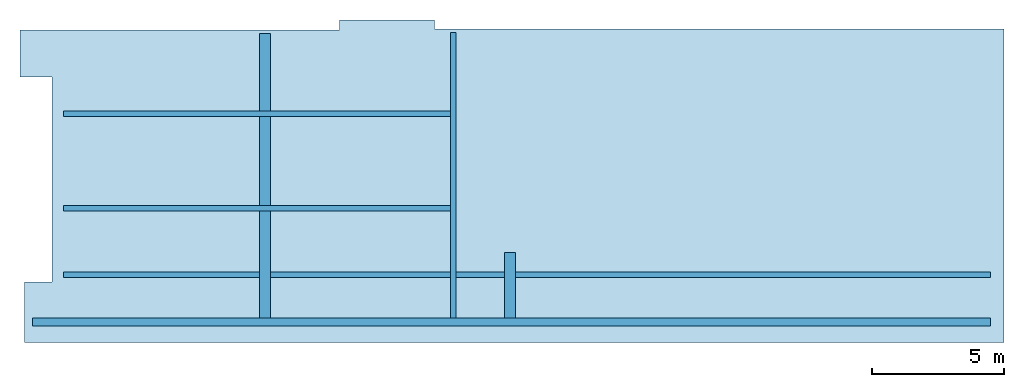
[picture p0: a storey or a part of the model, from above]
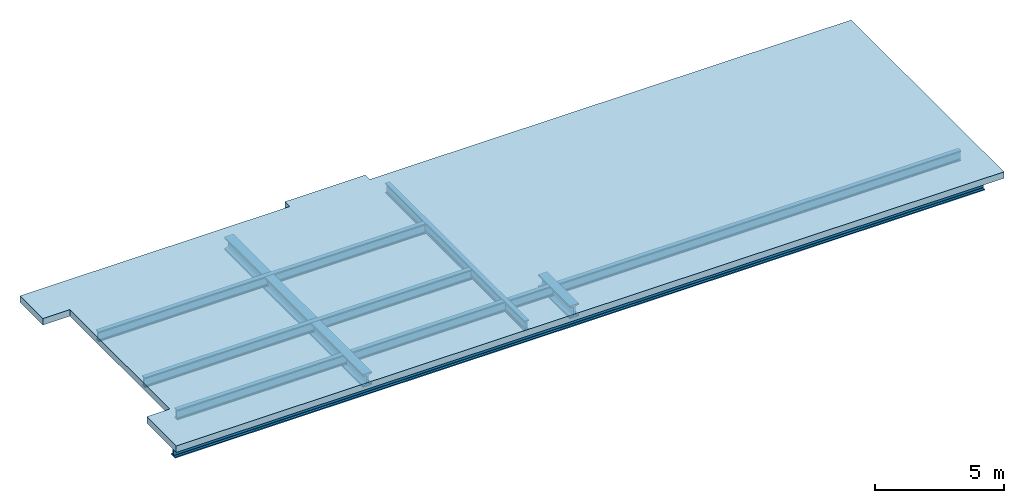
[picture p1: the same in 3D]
Properties of the parts of a building model (IFC4), part 1 of 2

# File
Description: ViewDefinition [DesignTransferView_V1.0]
File name: Project Number
Time: 2022-08-30T19:12:37
Written by: The EXPRESS Data Manager Version 5.02.0100.07 : 28 Aug 2013
Made in: 20200210_1400(x64) - Exporter 20.2.12.1 - Alternate UI 20.2.12.1
Comment: STEP Physical File produced by: The EXPRESS Data Manager Version 5.02.0100.07 : 28 Aug 2013 * Module: EDMstepFileFactory/EDMstandAlone * Creation date: Tue Aug 30 19:12:37 2022 * Host: DESKTOP-ASMPUQ8 * Database: C:\Users\PA\AppData\Local\Temp\d3cd8c80-7526-4842-971e-067392d3ef80\bd1fe66a-f83b-4d99-8f8f-0db7dfb2baac\ifc * Database version: 5507 * Database creation date: Tue Aug 30 19:12:32 2022 * Schema: IFC4 * Model: DataRepository.ifc * Model creation date: Tue Aug 30 19:12:32 2022 * Header model: DataRepository.ifc_HeaderModel * Header model creation date: Tue Aug 30 19:12:32 2022 * EDMuser: sdai-user * EDMgroup: sdai-group * License ID and type: 5605 : Permanent license. Expiry date: * EDMstepFileFactory options: 020000

# IfcProject, Project Number
LongName: NY 1114 6th Ave L15; Phase: Project Status

# IfcSite, Default
RefLatitude: 42, 21, 31, 181945; RefLongitude: -71, -3, -24, -263305; RefElevation: 0 ft

# IfcBuilding
Pset_BuildingCommon - Reference: Project Information; NumberOfStoreys: 3

# IfcBuildingStorey: Level:1/4" Head (3)
Pset_BuildingStoreyCommon - Reference: 1/4" Head
Name | LongName | Elevation (ft)
Level 3 | Level 3 | 24
Level 15 | Level 15 | 168
Level 16 | Level 16 | 181.083

# IfcAirTerminal: 10'-6" (2)
In: Level 15
Type - Pset_AirTerminalTypeCommon - Reference: 10'-6"; SlotWidth: 0.0833333 ft
Type - Pset_EnvironmentalImpactIndicators - Reference: 10'-6"
Name (Supply Diffuser with Plenum - Linear Slot - Hosted:10'-6":...)
2782970
2783304

# IfcAirTerminal: 12' (4)
In: Level 15
Type - Pset_AirTerminalTypeCommon - Reference: 12'; SlotWidth: 0.0833333 ft
Type - Pset_EnvironmentalImpactIndicators - Reference: 12'
Name (Supply Diffuser with Plenum - Linear Slot - Hosted:12':...)
2778098
2782745
2782873
2782875

# IfcAirTerminal: 16', Supply Diffuser with Plenum - Linear Slot - Hosted:16':2783469
In: Level 15
Type - Pset_AirTerminalTypeCommon - Reference: 16'; SlotWidth: 0.0833333 ft
Type - Pset_EnvironmentalImpactIndicators - Reference: 16'

# IfcAirTerminal: 16x10 (3)
In: Level 15
Type - Pset_AirTerminalTypeCommon - Reference: 16x10
Type - Pset_EnvironmentalImpactIndicators - Reference: 16x10
Pset_AirTerminalTypeCommon - sets with these values: 2
Group: Mechanical Supply Air 12
Name (Supply Diffuser - Sidewall:16x10:...)
2730207
2730213
2730216

# IfcAirTerminal: 20 x 20, Square Supply Diffuser (1):20 x 20:2646494
In: Level 15
Type - Classification: D3040100 Air Distribution Systems (Uniformat)
Type - Pset_AirTerminalTypeCommon - Reference: 20 x 20
Type - Pset_EnvironmentalImpactIndicators - Reference: 20 x 20
Pset_AirTerminalTypeCommon - sets with these values: 2

# IfcAirTerminal: 20x14 (3)
In: Level 15
Type - Pset_AirTerminalTypeCommon - Reference: 20x14
Type - Pset_EnvironmentalImpactIndicators - Reference: 20x14
Pset_AirTerminalTypeCommon - sets with these values: 2
Group: Mechanical Supply Air 7
Name (Supply Diffuser - Sidewall:20x14:...)
2730194
2730197
2730199

# IfcAirTerminal: 24x 24 (2)
In: Level 15
Type - Classification: D3040100 Air Distribution Systems (Uniformat)
Type - Pset_AirTerminalTypeCommon - Reference: 24x 24
Type - Pset_EnvironmentalImpactIndicators - Reference: 24x 24
Pset_AirTerminalTypeCommon - sets with these values: 2
Name (Square Supply Diffuser (1):24x 24:...)
2646642
2646688

# IfcAirTerminal: 32x12 (3)
In: Level 15
Type - Pset_AirTerminalTypeCommon - Reference: 32x12
Type - Pset_EnvironmentalImpactIndicators - Reference: 32x12
Pset_AirTerminalTypeCommon - sets with these values: 2
Name (Supply Diffuser - Sidewall:32x12:...) | Group
2730180 | Mechanical Supply Air 2
2730182 | Mechanical Supply Air 2
2730186 | Mechanical Supply Air 4

# IfcAirTerminal: 46'-6" (2)
In: Level 15
Type - Pset_AirTerminalTypeCommon - Reference: 46'-6"; SlotWidth: 0.0833333 ft
Type - Pset_EnvironmentalImpactIndicators - Reference: 46'-6"
Name (Supply Diffuser with Plenum - Linear Slot - Hosted:46'-6":...)
2783690
2783849

# IfcAirTerminal: 50x20, Supply Diffuser - Sidewall:50x20:2730433
In: Level 15
Type - Pset_AirTerminalTypeCommon - Reference: 50x20
Type - Pset_EnvironmentalImpactIndicators - Reference: 50x20
Pset_AirTerminalTypeCommon - sets with these values: 2
Group: Mechanical Supply Air 19

# IfcBeam: T Form Beam (4)
In: Level 16
Type - PredefinedType: BEAM; Material: Steel, 45-345
Type - Pset_BeamCommon - IsExternal: no; Reference: T Form Beam
Type - Pset_EnvironmentalImpactIndicators - Reference: T Form Beam
Type - Pset_ReinforcementBarPitchOfBeam - Reference: T Form Beam
Pset_BeamCommon - Slope: 0 deg; Roll: 0 deg
Pset_EnvironmentalImpactIndicators - sets with these values: 2
Name (UB-Universal Beam:T Form Beam:...) | Span (ft)
2719749 | 49.6875
2720074 | 49.0208
2720323 | 116.959
2722082 | 37.4165

# IfcBeam: T Form Beam 2 (2)
In: Level 16
Type - PredefinedType: BEAM; Material: Steel, 45-345
Type - Pset_BeamCommon - IsExternal: no; Reference: T Form Beam 2
Type - Pset_EnvironmentalImpactIndicators - Reference: T Form Beam 2
Type - Pset_ReinforcementBarPitchOfBeam - Reference: T Form Beam 2
Pset_BeamCommon - Slope: 0 deg; Roll: 0 deg
Pset_EnvironmentalImpactIndicators - sets with these values: 2
Name (UB-Universal Beam:T Form Beam 2:...) | Span (ft)
2721637 | 34.5559
2722027 | 7.31925

# IfcBeam: T Form Beam 3, UB-Universal Beam:T Form Beam 3:2722767
In: Level 16
Type - PredefinedType: BEAM; Material: Steel, 45-345
Type - Pset_BeamCommon - IsExternal: no; Reference: T Form Beam 3
Type - Pset_EnvironmentalImpactIndicators - Reference: T Form Beam 3
Type - Pset_ReinforcementBarPitchOfBeam - Reference: T Form Beam 3
Pset_BeamCommon - Slope: 0 deg; Roll: 0 deg; Span: 116.959 ft
Pset_EnvironmentalImpactIndicators - sets with these values: 2

# IfcBuildingElementProxy: Electrical Equipment, Electrical Equipment:Electrical Equipment:2730397
In: Level 15
Type - Pset_BuildingElementProxyCommon - IsExternal: no; Reference: Electrical Equipment
Type - Pset_EnvironmentalImpactIndicators - Reference: Electrical Equipment
Pset_BuildingElementProxyProvisionForVoid - Width: 2 ft; Height: 0.833333 ft; Depth: 2.5 ft

# IfcBuildingElementProxy: Mechanical Equipment_Unit 01, Mechanical Equipment_Unit 01:Mechanical Equipment_Unit 01:2730187
In: Level 15
Type - Pset_BuildingElementProxyCommon - IsExternal: no; Reference: Mechanical Equipment_Unit 01
Type - Pset_BuildingElementProxyProvisionForVoid - Width: 10.8333 ft; Height: 3.58333 ft; Depth: 10 ft
Type - Pset_EnvironmentalImpactIndicators - Reference: Mechanical Equipment_Unit 01

# IfcBuildingElementProxy: Radiator (4)
In: Level 15
Type - Pset_BuildingElementProxyCommon - IsExternal: no; Reference: Radiator
Type - Pset_EnvironmentalImpactIndicators - Reference: Radiator
Pset_BuildingElementProxyProvisionForVoid - Width: 1.72581 ft; Depth: 1.72581 ft
Name | Height (ft)
Radiator:Radiator:2247199 | 27.1817
Radiator1:Radiator:2247215 | 2.67119
Radiator2:Radiator:2247271 | 27.2291
Radiator3:Radiator:2247353 | 2.67119

# IfcCableCarrierFitting: Standard (9)
In: Level 15
Type - Pset_CableCarrierFittingTypeCommon - Reference: Standard
Type - Pset_EnvironmentalImpactIndicators - Reference: Standard
Pset_CableCarrierFittingTypeCommon - sets with these values: 2
Name (Conduit Elbow - Steel:Standard:...)
2730395
2730408
2730595
2730597
2730599
2730604
2730606
2730664
2730667

# IfcCableCarrierSegment: Conduit with Fittings:Conduit (16)
In: Level 15
Type - Pset_CableCarrierSegmentTypeCommon - Reference: Conduit
Type - Pset_EnvironmentalImpactIndicators - Reference: Conduit
Pset_CableCarrierSegmentTypeCommon - sets with these values: 2
Name (Conduit with Fittings:Conduit:...)
2730393
2730394
2730398
2730407
2730591
2730592
2730593
2730594
2730601
2730602
2730603
2730660
2730661
2730662
2730663
2730666

# IfcColumn: Generic (5)
In: Level 15
Type - PredefinedType: COLUMN; Classification: B1010200 Upper Floor Framing - Vertical Elements (Uniformat); Material: Default Wall
Type - Pset_ColumnCommon - IsExternal: no; Reference: Generic
Type - Pset_EnvironmentalImpactIndicators - Reference: Generic
Type - Pset_ReinforcementBarPitchOfColumn - Reference: Generic
Pset_ColumnCommon - Slope: 0 deg
Pset_EnvironmentalImpactIndicators - sets with these values: 2
Name (I-Rectangular:Generic:...)
2212022
2212228
2212427
2212525
2212709

# IfcCovering: Compound Ceiling:30" x 30" ACT System (3)
In: Level 15
Type - PredefinedType: CEILING
Type - Pset_CoveringCommon - IsExternal: no; Reference: 30" x 30" ACT System; ThermalTransmittance: 3.59055 kg/K/s3
Type - Pset_EnvironmentalImpactIndicators - Reference: 30" x 30" ACT System
Classification: C3030210 Suspended Ceilings - Acoustical (Uniformat); Material: Default 0.135417 ft, Acoustic Ceiling Tile 24 x 24 0.0520833 ft
Pset_CoveringCommon - Finish: Acoustic Ceiling Tile 24 x 24;
Name (Compound Ceiling:30" x 30" ACT System:...)
2594296
2594552
2594579

# IfcCovering: Compound Ceiling:GWB on Mtl. Stud (4)
In: Level 15
Type - PredefinedType: CEILING
Type - Pset_CoveringCommon - IsExternal: no; Reference: GWB on Mtl. Stud; ThermalTransmittance: 0.271518 kg/K/s3
Type - Pset_EnvironmentalImpactIndicators - Reference: GWB on Mtl. Stud
Classification: C3030220 Suspended Ceilings - Gypsum Board (Uniformat); Material: Metal Stud Layer 0.302083 ft
Name (Compound Ceiling:GWB on Mtl. Stud:...)
2593632
2593987
2776662
2776686

# IfcCovering: Pipe Insulation:Default (11)
In: Level 15
PredefinedType: INSULATION
Pset_CoveringCommon - IsExternal: no; Reference: Default
Pset_EnvironmentalImpactIndicators - Reference: Default
Name (Pipe Insulation:Default:...)
2776108
2776109
2776110
2776111
2776112
2776113
2776122
2776123
2776124
2776125
2776126

# IfcCurtainWall: Curtain Wall:Storefront (5)
In: Level 15
Type - Pset_CurtainWallCommon - IsExternal: no; Reference: Storefront
Type - Pset_EnvironmentalImpactIndicators - Reference: Storefront
Classification: B2020200 Curtain Walls (Uniformat)
Pset_CurtainWallCommon - IsExternal: yes
Name (Curtain Wall:Storefront:...)
2237436
2238658
2246862
2246942
2247033

# IfcCurtainWall: Curtain Wall:Storefront 02 (12)
In: Level 15
Type - Pset_CurtainWallCommon - IsExternal: no; Reference: Storefront 02
Type - Pset_EnvironmentalImpactIndicators - Reference: Storefront 02
Classification: B2020200 Curtain Walls (Uniformat)
Pset_CurtainWallCommon - IsExternal: yes
Name (Curtain Wall:Storefront 02:...)
2251181
2251577
2251802
2252624
2252727
2376070
2376076
2376082
2376088
2376094
2589335
2591836

# IfcDistributionPort (646)
Description: Flow
Name | FlowDirection | Group
Port_2616530 | SOURCEANDSINK
Port_2634564 | SOURCEANDSINK
Port_2642526 | SOURCEANDSINK
Port_2642614 | SOURCEANDSINK
Port_2642695 | SOURCEANDSINK
Port_2642750 | SOURCEANDSINK
Port_2642807 | SOURCEANDSINK
Port_2642872 | SOURCEANDSINK
Port_2642874 | SOURCEANDSINK
Port_2642875 | SOURCEANDSINK
Port_2642876 | SOURCEANDSINK
Port_2642877 | SOURCEANDSINK
Port_2642889 | SOURCEANDSINK
Port_2642944 | SOURCEANDSINK
Port_2642991 | SOURCEANDSINK
Port_2643043 | SOURCEANDSINK
Port_2643100 | SOURCEANDSINK
Port_2643161 | SOURCEANDSINK
Port_2643180 | SOURCEANDSINK
Port_2643225 | SOURCEANDSINK
Port_2643266 | SOURCEANDSINK
Port_2643285 | SOURCEANDSINK
Port_2643315 | SOURCEANDSINK
Port_2643362 | SOURCEANDSINK
Port_2643445 | SOURCEANDSINK
Port_2643491 | SOURCEANDSINK
Port_2643562 | SOURCEANDSINK
Port_2643622 | SOURCEANDSINK
Port_2643695 | SOURCEANDSINK
Port_2643761 | SOURCEANDSINK
Port_2643844 | SOURCEANDSINK
Port_2643890 | SOURCEANDSINK
Port_2643984 | SOURCEANDSINK
Port_2644073 | SOURCEANDSINK
Port_2644150 | SOURCEANDSINK
Port_2644226 | SOURCEANDSINK
Port_2645126 | SOURCEANDSINK
Port_2645178 | SOURCEANDSINK
Port_2645256 | SOURCEANDSINK
Port_2645257 | SOURCEANDSINK
Port_2645316 | SOURCEANDSINK
Port_2645411 | SOURCEANDSINK
Port_2645462 | SOURCEANDSINK
Port_2645515 | SOURCEANDSINK
Port_2645580 | SOURCEANDSINK
Port_2645619 | SOURCEANDSINK
Port_2645707 | SOURCEANDSINK
Port_2645776 | SOURCEANDSINK
Port_2645860 | SOURCEANDSINK
Port_2646268 | SOURCEANDSINK
Port_2646331 | SOURCEANDSINK
Port_2648358 | SOURCEANDSINK
3 x InPort_2730176 | SOURCEANDSINK | Mechanical Supply Air 2
OutPort_2730178 | SOURCEANDSINK | Mechanical Supply Air 2
2 x OutPort_2730181 | SOURCEANDSINK | Mechanical Supply Air 2
2 x OutPort_2730670 | SOURCEANDSINK | Mechanical Supply Air 2
3 x InPort_2730177 | SOURCEANDSINK | Mechanical Supply Air 2
OutPort_2730669 | SOURCEANDSINK | Mechanical Supply Air 2
2 x OutPort_2730184 | SOURCEANDSINK | Mechanical Supply Air 2
2 x InPort_2730179 | SOURCEANDSINK | Mechanical Supply Air 2
OutPort_2730180 | SOURCEANDSINK | Mechanical Supply Air 2
InPort_2730180 | SINK | Mechanical Supply Air 2
OutPort_2730179 | SOURCE | Mechanical Supply Air 2
InPort_2730182 | SINK | Mechanical Supply Air 2
OutPort_2730183 | SOURCE | Mechanical Supply Air 2
InPort_2730183 | SOURCEANDSINK | Mechanical Supply Air 2
2 x InPort_2730185 | SOURCEANDSINK | Mechanical Supply Air 4
2 x OutPort_2730675 | SOURCEANDSINK | Mechanical Supply Air 4
OutPort_2730186 | SOURCEANDSINK | Mechanical Supply Air 4
InPort_2730186 | SINK | Mechanical Supply Air 4
OutPort_2730185 | SOURCE | Mechanical Supply Air 4
InPort_2730188 | SOURCEANDSINK | Mechanical Supply Air 5
2 x OutPort_2730677 | SOURCEANDSINK | Mechanical Supply Air 5
InPort_2730189 | SOURCEANDSINK | Mechanical Supply Air 7
OutPort_2730191 | SOURCEANDSINK | Mechanical Supply Air 7
2 x InPort_2730190 | SOURCEANDSINK | Mechanical Supply Air 7
2 x OutPort_2730192 | SOURCEANDSINK | Mechanical Supply Air 7
OutPort_2730193 | SOURCEANDSINK | Mechanical Supply Air 7
3 x InPort_2730191 | SOURCEANDSINK | Mechanical Supply Air 7
2 x OutPort_2730196 | SOURCEANDSINK | Mechanical Supply Air 7
2 x OutPort_2730201 | SOURCEANDSINK | Mechanical Supply Air 7
InPort_2730193 | SOURCEANDSINK | Mechanical Supply Air 7
2 x OutPort_2730203 | SOURCEANDSINK | Mechanical Supply Air 7
InPort_2730194 | SINK | Mechanical Supply Air 7
OutPort_2730195 | SOURCE | Mechanical Supply Air 7
InPort_2730195 | SOURCEANDSINK | Mechanical Supply Air 7
InPort_2730197 | SINK | Mechanical Supply Air 7
OutPort_2730198 | SOURCE | Mechanical Supply Air 7
InPort_2730198 | SOURCEANDSINK | Mechanical Supply Air 7
OutPort_2730202 | SOURCEANDSINK | Mechanical Supply Air 7
InPort_2730199 | SINK | Mechanical Supply Air 7
OutPort_2730200 | SOURCE | Mechanical Supply Air 7
InPort_2730200 | SOURCEANDSINK | Mechanical Supply Air 7
InPort_2730202 | SOURCEANDSINK | Mechanical Supply Air 7
InPort_2730203 | SOURCEANDSINK | Mechanical Supply Air 7
OutPort_2730204 | SOURCEANDSINK | Mechanical Supply Air 7
Port_2730204 | SOURCEANDSINK | Mechanical Supply Air 7
InPort_2730205 | SOURCEANDSINK | Mechanical Supply Air 12
OutPort_2730209 | SOURCEANDSINK | Mechanical Supply Air 12
2 x InPort_2730206 | SOURCEANDSINK | Mechanical Supply Air 12
OutPort_2730208 | SOURCEANDSINK | Mechanical Supply Air 12
2 x OutPort_2730210 | SOURCEANDSINK | Mechanical Supply Air 12
InPort_2730207 | SINK | Mechanical Supply Air 12
OutPort_2730211 | SOURCE | Mechanical Supply Air 12
4 x InPort_2730209 | SOURCEANDSINK | Mechanical Supply Air 12
2 x OutPort_2730218 | SOURCEANDSINK | Mechanical Supply Air 12
2 x OutPort_2730212 | SOURCEANDSINK | Mechanical Supply Air 12
2 x OutPort_2730215 | SOURCEANDSINK | Mechanical Supply Air 12
InPort_2730211 | SOURCEANDSINK | Mechanical Supply Air 12
InPort_2730213 | SINK | Mechanical Supply Air 12
OutPort_2730214 | SOURCE | Mechanical Supply Air 12
InPort_2730214 | SOURCEANDSINK | Mechanical Supply Air 12
InPort_2730216 | SINK | Mechanical Supply Air 12
OutPort_2730217 | SOURCE | Mechanical Supply Air 12
InPort_2730217 | SOURCEANDSINK | Mechanical Supply Air 12
Port_2730219 | SOURCEANDSINK | Fire Protection Wet 2
InPort_2730219 | SOURCEANDSINK | Fire Protection Wet 2
2 x OutPort_2730403 | SOURCEANDSINK | Fire Protection Wet 2
2 x InPort_2730221 | SOURCEANDSINK | Fire Protection Wet 2
OutPort_2730223 | SOURCEANDSINK | Fire Protection Wet 2
2 x OutPort_2730227 | SOURCEANDSINK | Fire Protection Wet 2
InPort_2730223 | SOURCEANDSINK | Fire Protection Wet 2
2 x OutPort_2730258 | SOURCEANDSINK | Fire Protection Wet 2
2 x InPort_2730225 | SOURCEANDSINK | Fire Protection Wet 2
2 x OutPort_2730231 | SOURCEANDSINK | Fire Protection Wet 2
2 x InPort_2730229 | SOURCEANDSINK | Fire Protection Wet 2
OutPort_2730241 | SOURCEANDSINK | Fire Protection Wet 2
2 x InPort_2730233 | SOURCEANDSINK | Mechanical Supply Air 16
2 x OutPort_2730413 | SOURCEANDSINK | Mechanical Supply Air 16
OutPort_2730234 | SOURCEANDSINK | Mechanical Supply Air 16
InPort_2730234 | SOURCEANDSINK | Mechanical Supply Air 16
OutPort_2730235 | SOURCEANDSINK | Mechanical Supply Air 16
InPort_2730235 | SOURCEANDSINK | Mechanical Supply Air 16
OutPort_2730236 | SOURCEANDSINK | Mechanical Supply Air 16
Port_2730236 | SOURCEANDSINK | Mechanical Supply Air 16
3 x InPort_2730237 | SOURCEANDSINK | Fire Protection Wet 2
2 x OutPort_2730400 | SOURCEANDSINK | Fire Protection Wet 2
2 x OutPort_2730249 | SOURCEANDSINK | Fire Protection Wet 2
OutPort_2730238 | SOURCEANDSINK | Fire Protection Wet 2
InPort_2730238 | SOURCEANDSINK | Fire Protection Wet 2
2 x OutPort_2730436 | SOURCEANDSINK | Fire Protection Wet 2
InPort_2730241 | SOURCEANDSINK | Fire Protection Wet 2
OutPort_2730246 | SOURCEANDSINK | Fire Protection Wet 2
InPort_2730243 | SINK | Fire Protection Wet 2
OutPort_2730244 | SOURCE | Fire Protection Wet 2
InPort_2730244 | SOURCEANDSINK | Fire Protection Wet 2
2 x OutPort_2730248 | SOURCEANDSINK | Fire Protection Wet 2
InPort_2730246 | SOURCEANDSINK | Fire Protection Wet 2
InPort_2730248 | SOURCEANDSINK | Fire Protection Wet 2
InPort_2730252 | SINK | Fire Protection Wet 2
OutPort_2730253 | SOURCE | Fire Protection Wet 2
InPort_2730253 | SOURCEANDSINK | Fire Protection Wet 2
2 x OutPort_2730257 | SOURCEANDSINK | Fire Protection Wet 2
2 x InPort_2730255 | SOURCEANDSINK | Fire Protection Wet 2
2 x OutPort_2730264 | SOURCEANDSINK | Fire Protection Wet 2
InPort_2730257 | SOURCEANDSINK | Fire Protection Wet 2
InPort_2730261 | SINK | Fire Protection Wet 2
OutPort_2730262 | SOURCE | Fire Protection Wet 2
InPort_2730262 | SOURCEANDSINK | Fire Protection Wet 2
2 x InPort_2730266 | SOURCEANDSINK | Fire Protection Wet 2
2 x OutPort_2730349 | SOURCEANDSINK | Fire Protection Wet 2
2 x OutPort_2730270 | SOURCEANDSINK | Fire Protection Wet 2
2 x InPort_2730268 | SOURCEANDSINK | Fire Protection Wet 2
2 x OutPort_2730274 | SOURCEANDSINK | Fire Protection Wet 2
2 x InPort_2730272 | SOURCEANDSINK | Fire Protection Wet 2
OutPort_2730276 | SOURCEANDSINK | Fire Protection Wet 2
InPort_2730276 | SOURCEANDSINK | Fire Protection Wet 2
OutPort_2730280 | SOURCEANDSINK | Fire Protection Wet 2
Port_2730278 | SOURCEANDSINK | Fire Protection Wet 2
InPort_2730278 | SOURCEANDSINK | Fire Protection Wet 2
2 x OutPort_2730282 | SOURCEANDSINK | Fire Protection Wet 2
InPort_2730280 | SOURCEANDSINK | Fire Protection Wet 2
InPort_2730282 | SOURCEANDSINK | Fire Protection Wet 2
OutPort_2730283 | SOURCEANDSINK | Fire Protection Wet 2
InPort_2730283 | SOURCEANDSINK | Fire Protection Wet 2
OutPort_2730399 | SOURCEANDSINK | Fire Protection Wet 2
2 x InPort_2730286 | SOURCEANDSINK | Fire Protection Wet 2
2 x OutPort_2730347 | SOURCEANDSINK | Fire Protection Wet 2
OutPort_2730290 | SOURCEANDSINK | Fire Protection Wet 2
2 x InPort_2730288 | SOURCEANDSINK | Fire Protection Wet 2
2 x OutPort_2730297 | SOURCEANDSINK | Fire Protection Wet 2
2 x OutPort_2730337 | SOURCEANDSINK | Fire Protection Wet 2
2 x InPort_2730290 | SOURCEANDSINK | Fire Protection Wet 2
OutPort_2730291 | SOURCEANDSINK | Fire Protection Wet 2
OutPort_2730327 | SOURCEANDSINK | Fire Protection Wet 2
InPort_2730291 | SOURCEANDSINK | Fire Protection Wet 2
2 x OutPort_2730343 | SOURCEANDSINK | Fire Protection Wet 2
InPort_2730294 | SINK | Fire Protection Wet 2
OutPort_2730295 | SOURCE | Fire Protection Wet 2
InPort_2730295 | SOURCEANDSINK | Fire Protection Wet 2
2 x InPort_2730299 | SOURCEANDSINK | Fire Protection Wet 2
2 x OutPort_2730367 | SOURCEANDSINK | Fire Protection Wet 2
OutPort_2730301 | SOURCEANDSINK | Fire Protection Wet 2
InPort_2730301 | SOURCEANDSINK | Fire Protection Wet 2
2 x OutPort_2730319 | SOURCEANDSINK | Fire Protection Wet 2
2 x InPort_2730303 | SOURCEANDSINK | Fire Protection Wet 2
2 x OutPort_2730307 | SOURCEANDSINK | Fire Protection Wet 2
2 x OutPort_2730371 | SOURCEANDSINK | Fire Protection Wet 2
2 x InPort_2730305 | SOURCEANDSINK | Fire Protection Wet 2
OutPort_2730309 | SOURCEANDSINK | Fire Protection Wet 2
InPort_2730309 | SOURCEANDSINK | Fire Protection Wet 2
OutPort_2730311 | SOURCEANDSINK | Fire Protection Wet 2
InPort_2730311 | SOURCEANDSINK | Fire Protection Wet 2
2 x OutPort_2730378 | SOURCEANDSINK | Fire Protection Wet 2
InPort_2730313 | SINK | Fire Protection Wet 2
OutPort_2730314 | SOURCE | Fire Protection Wet 2
InPort_2730314 | SOURCEANDSINK | Fire Protection Wet 2
OutPort_2730318 | SOURCEANDSINK | Fire Protection Wet 2
2 x InPort_2730316 | SOURCEANDSINK | Fire Protection Wet 2
2 x OutPort_2730361 | SOURCEANDSINK | Fire Protection Wet 2
2 x OutPort_2730325 | SOURCEANDSINK | Fire Protection Wet 2
2 x InPort_2730318 | SOURCEANDSINK | Fire Protection Wet 2
OutPort_2730357 | SOURCEANDSINK | Fire Protection Wet 2
InPort_2730322 | SINK | Fire Protection Wet 2
OutPort_2730323 | SOURCE | Fire Protection Wet 2
InPort_2730323 | SOURCEANDSINK | Fire Protection Wet 2
InPort_2730327 | SOURCEANDSINK | Fire Protection Wet 2
2 x OutPort_2730333 | SOURCEANDSINK | Fire Protection Wet 2
2 x InPort_2730329 | SOURCEANDSINK | Fire Protection Wet 2
2 x OutPort_2730335 | SOURCEANDSINK | Fire Protection Wet 2
2 x InPort_2730331 | SOURCEANDSINK | Fire Protection Wet 2
2 x InPort_2730339 | SOURCEANDSINK | Fire Protection Wet 2
2 x OutPort_2730351 | SOURCEANDSINK | Fire Protection Wet 2
2 x InPort_2730341 | SOURCEANDSINK | Fire Protection Wet 2
2 x InPort_2730345 | SOURCEANDSINK | Fire Protection Wet 2
2 x OutPort_2730355 | SOURCEANDSINK | Fire Protection Wet 2
Port_2730353 | SOURCEANDSINK | Fire Protection Wet 2
InPort_2730353 | SOURCEANDSINK | Fire Protection Wet 2
InPort_2730357 | SOURCEANDSINK | Fire Protection Wet 2
2 x OutPort_2730363 | SOURCEANDSINK | Fire Protection Wet 2
2 x InPort_2730359 | SOURCEANDSINK | Fire Protection Wet 2
2 x InPort_2730365 | SOURCEANDSINK | Fire Protection Wet 2
2 x OutPort_2730373 | SOURCEANDSINK | Fire Protection Wet 2
2 x InPort_2730369 | SOURCEANDSINK | Fire Protection Wet 2
InPort_2730375 | SINK | Fire Protection Wet 2
OutPort_2730376 | SOURCE | Fire Protection Wet 2
InPort_2730376 | SOURCEANDSINK | Fire Protection Wet 2
InPort_2730378 | SOURCEANDSINK | Fire Protection Wet 2
OutPort_2730379 | SOURCEANDSINK | Fire Protection Wet 2
InPort_2730379 | SOURCEANDSINK | Fire Protection Wet 2
2 x InPort_2730382 | SOURCEANDSINK | Fire Protection Wet 11
2 x OutPort_2730391 | SOURCEANDSINK | Fire Protection Wet 11
2 x OutPort_2730387 | SOURCEANDSINK | Fire Protection Wet 11
InPort_2730384 | SINK | Fire Protection Wet 11
OutPort_2730385 | SOURCE | Fire Protection Wet 11
InPort_2730385 | SOURCEANDSINK | Fire Protection Wet 11
InPort_2730389 | SOURCEANDSINK | Fire Protection Wet 11
Port_2730389 | SOURCEANDSINK | Fire Protection Wet 11
Port_2730393 | SOURCEANDSINK
InPort_2730393 | SOURCEANDSINK
2 x OutPort_2730395 | SOURCEANDSINK
InPort_2730394 | SOURCEANDSINK
Port_2730394 | SOURCEANDSINK
InPort_2730398 | SOURCEANDSINK
2 x OutPort_2730408 | SOURCEANDSINK
Port_2730398 | SOURCEANDSINK
2 x InPort_2730399 | SOURCEANDSINK | Fire Protection Wet 2
2 x OutPort_2730404 | SOURCEANDSINK | Fire Protection Wet 2
InPort_2730403 | SOURCEANDSINK | Fire Protection Wet 2
InPort_2730407 | SOURCEANDSINK
Port_2730407 | SOURCEANDSINK
Port_2730410 | SOURCEANDSINK | Mechanical Supply Air 16
InPort_2730410 | SOURCEANDSINK | Mechanical Supply Air 16
2 x OutPort_2730412 | SOURCEANDSINK | Mechanical Supply Air 16
2 x InPort_2730411 | SOURCEANDSINK | Mechanical Supply Air 16
2 x InPort_2730414 | SOURCEANDSINK | Hydronic Supply 1
2 x OutPort_2730420 | SOURCEANDSINK | Hydronic Supply 1
2 x OutPort_2730495 | SOURCEANDSINK | Hydronic Supply 1
2 x InPort_2730416 | SOURCEANDSINK | Hydronic Supply 1
2 x OutPort_2730543 | SOURCEANDSINK | Hydronic Supply 1
2 x OutPort_2730426 | SOURCEANDSINK | Hydronic Supply 1
2 x InPort_2730418 | SOURCEANDSINK | Hydronic Supply 1
OutPort_2730422 | SOURCEANDSINK | Hydronic Supply 1
InPort_2730422 | SOURCEANDSINK | Hydronic Supply 1
2 x OutPort_2730544 | SOURCEANDSINK | Hydronic Supply 1
2 x InPort_2730424 | SOURCEANDSINK | Hydronic Supply 1
2 x OutPort_2730430 | SOURCEANDSINK | Hydronic Supply 1
Port_2730428 | SOURCEANDSINK | Hydronic Supply 1
InPort_2730428 | SOURCEANDSINK | Hydronic Supply 1
InPort_2730432 | SOURCEANDSINK | Mechanical Supply Air 19
OutPort_2730433 | SOURCEANDSINK | Mechanical Supply Air 19
Port_2730432 | SOURCEANDSINK | Mechanical Supply Air 19
InPort_2730433 | SINK | Mechanical Supply Air 19
OutPort_2730432 | SOURCE | Mechanical Supply Air 19
2 x InPort_2730434 | SOURCEANDSINK | Fire Protection Wet 2
2 x OutPort_2730440 | SOURCEANDSINK | Fire Protection Wet 2
InPort_2730438 | SOURCEANDSINK | Fire Protection Wet 2
Port_2730438 | SOURCEANDSINK | Fire Protection Wet 2
2 x InPort_2730442 | SOURCEANDSINK | Other 1
2 x OutPort_2730475 | SOURCEANDSINK | Other 1
OutPort_2730473 | SOURCEANDSINK | Other 1
2 x InPort_2730444 | SOURCEANDSINK | Fire Protection Wet 14
2 x OutPort_2730450 | SOURCEANDSINK | Fire Protection Wet 14
OutPort_2730446 | SOURCEANDSINK | Fire Protection Wet 14
Port_2730446 | SINK | Fire Protection Wet 14
2 x InPort_2730448 | SOURCEANDSINK | Fire Protection Wet 14
2 x OutPort_2730461 | SOURCEANDSINK | Fire Protection Wet 14
Port_2730452 | SOURCEANDSINK | Fire Protection Wet 16
InPort_2730452 | SOURCEANDSINK | Fire Protection Wet 16
2 x OutPort_2730457 | SOURCEANDSINK | Fire Protection Wet 16
InPort_2730454 | SINK | Fire Protection Wet 16
OutPort_2730455 | SOURCE | Fire Protection Wet 16
InPort_2730455 | SOURCEANDSINK | Fire Protection Wet 16
InPort_2730459 | SOURCEANDSINK | Fire Protection Wet 14
Port_2730459 | SOURCEANDSINK | Fire Protection Wet 14
InPort_2730463 | SOURCEANDSINK | Other 1
2 x OutPort_2730467 | SOURCEANDSINK | Other 1
Port_2730463 | SOURCEANDSINK | Other 1
2 x InPort_2730465 | SOURCEANDSINK | Other 1
InPort_2730467 | SOURCEANDSINK | Other 1
OutPort_2730468 | SOURCEANDSINK | Other 1
Port_2730468 | SOURCEANDSINK | Other 1
2 x InPort_2730471 | SOURCEANDSINK | Other 1
2 x OutPort_2730491 | SOURCEANDSINK | Other 1
2 x OutPort_2730483 | SOURCEANDSINK | Other 1
InPort_2730473 | SOURCEANDSINK | Other 1
OutPort_2730477 | SOURCEANDSINK | Other 1
InPort_2730477 | SOURCEANDSINK | Other 1
2 x OutPort_2730489 | SOURCEANDSINK | Other 1
InPort_2730479 | SOURCEANDSINK | Other 1
2 x OutPort_2730485 | SOURCEANDSINK | Other 1
Port_2730479 | SOURCEANDSINK | Other 1
2 x InPort_2730481 | SOURCEANDSINK | Other 1
2 x InPort_2730487 | SOURCEANDSINK | Other 1
2 x InPort_2730493 | SOURCEANDSINK | Hydronic Supply 1
2 x OutPort_2730499 | SOURCEANDSINK | Hydronic Supply 1
Port_2730497 | SOURCEANDSINK | Hydronic Supply 1
InPort_2730497 | SOURCEANDSINK | Hydronic Supply 1
2 x InPort_2730501 | SOURCEANDSINK | Hydronic Supply 3
2 x OutPort_2730507 | SOURCEANDSINK | Hydronic Supply 3
2 x OutPort_2730521 | SOURCEANDSINK | Hydronic Supply 3
2 x InPort_2730503 | SOURCEANDSINK | Hydronic Supply 3
2 x OutPort_2730573 | SOURCEANDSINK | Hydronic Supply 3
2 x OutPort_2730513 | SOURCEANDSINK | Hydronic Supply 3
2 x InPort_2730505 | SOURCEANDSINK | Hydronic Supply 3
OutPort_2730509 | SOURCEANDSINK | Hydronic Supply 3
InPort_2730509 | SOURCEANDSINK | Hydronic Supply 3
2 x OutPort_2730574 | SOURCEANDSINK | Hydronic Supply 3
2 x InPort_2730511 | SOURCEANDSINK | Hydronic Supply 3
2 x OutPort_2730517 | SOURCEANDSINK | Hydronic Supply 3
Port_2730515 | SOURCEANDSINK | Hydronic Supply 3
InPort_2730515 | SOURCEANDSINK | Hydronic Supply 3
2 x InPort_2730519 | SOURCEANDSINK | Hydronic Supply 3
2 x OutPort_2730525 | SOURCEANDSINK | Hydronic Supply 3
InPort_2730523 | SOURCEANDSINK | Hydronic Supply 3
Port_2730523 | SOURCEANDSINK | Hydronic Supply 3
2 x InPort_2730527 | SOURCEANDSINK | Hydronic Supply 1
2 x OutPort_2730531 | SOURCEANDSINK | Hydronic Supply 1
2 x OutPort_2730535 | SOURCEANDSINK | Hydronic Supply 1
Port_2730529 | SOURCEANDSINK | Hydronic Supply 1
InPort_2730529 | SOURCEANDSINK | Hydronic Supply 1
2 x InPort_2730533 | SOURCEANDSINK | Hydronic Supply 1
2 x OutPort_2730539 | SOURCEANDSINK | Hydronic Supply 1
2 x InPort_2730537 | SOURCEANDSINK | Hydronic Supply 1
2 x OutPort_2730547 | SOURCEANDSINK | Hydronic Supply 1
2 x InPort_2730541 | SOURCEANDSINK | Hydronic Supply 1
InPort_2730543 | SOURCEANDSINK | Hydronic Supply 1
2 x InPort_2730549 | SOURCEANDSINK | Hydronic Supply 3
2 x OutPort_2730557 | SOURCEANDSINK | Hydronic Supply 3
2 x OutPort_2730553 | SOURCEANDSINK | Hydronic Supply 3
2 x InPort_2730551 | SOURCEANDSINK | Hydronic Supply 3
2 x OutPort_2730567 | SOURCEANDSINK | Hydronic Supply 3
2 x InPort_2730555 | SOURCEANDSINK | Hydronic Supply 3
2 x OutPort_2730561 | SOURCEANDSINK | Hydronic Supply 3
2 x InPort_2730559 | SOURCEANDSINK | Hydronic Supply 3
2 x OutPort_2730577 | SOURCEANDSINK | Hydronic Supply 3
2 x InPort_2730563 | SOURCEANDSINK | Hydronic Supply 3
2 x InPort_2730565 | SOURCEANDSINK | Hydronic Supply 3
2 x OutPort_2730571 | SOURCEANDSINK | Hydronic Supply 3
Port_2730569 | SOURCEANDSINK | Hydronic Supply 3
InPort_2730569 | SOURCEANDSINK | Hydronic Supply 3
InPort_2730573 | SOURCEANDSINK | Hydronic Supply 3
InPort_2730579 | SOURCEANDSINK | Hydronic Supply 7
2 x OutPort_2730583 | SOURCEANDSINK | Hydronic Supply 7
Port_2730579 | SOURCEANDSINK | Hydronic Supply 7
Port_2730581 | SOURCEANDSINK | Hydronic Supply 7
InPort_2730581 | SOURCEANDSINK | Hydronic Supply 7
InPort_2730585 | SOURCEANDSINK | Hydronic Supply 9
2 x OutPort_2730589 | SOURCEANDSINK | Hydronic Supply 9
Port_2730585 | SOURCEANDSINK | Hydronic Supply 9
Port_2730587 | SOURCEANDSINK | Hydronic Supply 9
InPort_2730587 | SOURCEANDSINK | Hydronic Supply 9
2 x Port_2730591 | SOURCEANDSINK
2 x InPort_2730592 | SOURCEANDSINK
OutPort_2730599 | SOURCEANDSINK
2 x OutPort_2730595 | SOURCEANDSINK
2 x InPort_2730593 | SOURCEANDSINK
2 x OutPort_2730597 | SOURCEANDSINK
InPort_2730594 | SOURCEANDSINK
Port_2730594 | SOURCEANDSINK
Port_2730599 | SOURCEANDSINK
Port_2730601 | SOURCEANDSINK
InPort_2730601 | SOURCEANDSINK
2 x OutPort_2730604 | SOURCEANDSINK
2 x InPort_2730602 | SOURCEANDSINK
2 x OutPort_2730606 | SOURCEANDSINK
Port_2730603 | SOURCEANDSINK
InPort_2730603 | SOURCEANDSINK
InPort_2730608 | SOURCEANDSINK | Other 4
2 x OutPort_2730634 | SOURCEANDSINK | Other 4
Port_2730608 | SOURCEANDSINK | Other 4
2 x InPort_2730610 | SOURCEANDSINK | Other 4
2 x OutPort_2730618 | SOURCEANDSINK | Other 4
OutPort_2730612 | SOURCEANDSINK | Other 4
2 x InPort_2730612 | SOURCEANDSINK | Other 4
2 x OutPort_2730629 | SOURCEANDSINK | Other 4
OutPort_2730613 | SOURCEANDSINK | Other 4
Port_2730613 | SOURCEANDSINK | Other 4
InPort_2730616 | SOURCEANDSINK | Other 4
Port_2730616 | SOURCEANDSINK | Other 4
2 x InPort_2730620 | SOURCEANDSINK | Other 4
2 x OutPort_2730632 | SOURCEANDSINK | Other 4
OutPort_2730628 | SOURCEANDSINK | Other 4
Port_2730622 | SOURCEANDSINK | Other 4
InPort_2730622 | SOURCEANDSINK | Other 4
2 x InPort_2730624 | SOURCEANDSINK | Other 4
2 x OutPort_2730638 | SOURCEANDSINK | Other 4
Port_2730626 | SOURCEANDSINK | Other 4
InPort_2730626 | SOURCEANDSINK | Other 4
2 x InPort_2730628 | SOURCEANDSINK | Other 4
2 x OutPort_2730645 | SOURCEANDSINK | Other 4
InPort_2730634 | SOURCEANDSINK | Other 4
OutPort_2730635 | SOURCEANDSINK | Other 4
InPort_2730635 | SOURCEANDSINK | Other 4
2 x OutPort_2730654 | SOURCEANDSINK | Other 4
InPort_2730640 | SOURCEANDSINK | Other 4
2 x OutPort_2730648 | SOURCEANDSINK | Other 4
Port_2730640 | SOURCEANDSINK | Other 4
2 x InPort_2730642 | SOURCEANDSINK | Other 4
OutPort_2730644 | SOURCEANDSINK | Other 4
2 x InPort_2730644 | SOURCEANDSINK | Other 4
2 x OutPort_2730655 | SOURCEANDSINK | Other 4
InPort_2730650 | SOURCEANDSINK | Other 4
2 x OutPort_2730658 | SOURCEANDSINK | Other 4
Port_2730650 | SOURCEANDSINK | Other 4
2 x InPort_2730652 | SOURCEANDSINK | Other 4
InPort_2730654 | SOURCEANDSINK | Other 4
2 x Port_2730660 | SOURCEANDSINK
2 x Port_2730661 | SOURCEANDSINK
2 x InPort_2730662 | SOURCEANDSINK
2 x OutPort_2730667 | SOURCEANDSINK
2 x OutPort_2730664 | SOURCEANDSINK
InPort_2730663 | SOURCEANDSINK
Port_2730663 | SOURCEANDSINK
Port_2730666 | SOURCEANDSINK
InPort_2730666 | SOURCEANDSINK
InPort_2730669 | SOURCEANDSINK | Mechanical Supply Air 5
OutPort_2730676 | SOURCEANDSINK | Mechanical Supply Air 5
InPort_2730669 | SOURCEANDSINK | Mechanical Supply Air 4
OutPort_2730671 | SOURCEANDSINK | Mechanical Supply Air 4
InPort_2730671 | SOURCEANDSINK | Mechanical Supply Air 4
2 x OutPort_2730673 | SOURCEANDSINK | Mechanical Supply Air 4
3 x InPort_2730672 | SOURCEANDSINK | Mechanical Supply Air 4
OutPort_2730674 | SOURCEANDSINK | Mechanical Supply Air 4
InPort_2730676 | SOURCEANDSINK | Mechanical Supply Air 5

# IfcDoor: 36" x 102" (4)
In: Level 15
Type - PredefinedType: DOOR; ParameterTakesPrecedence: no; Material: Steel, Galvanized
Type - Pset_DoorCommon - IsExternal: no; Reference: 36" x 102"
Type - Pset_EnvironmentalImpactIndicators - Reference: 36" x 102"
OverallHeight: 8.53281 ft; OverallWidth: 3.06562 ft
Pset_DoorCommon - IsExternal: yes
Name (Door Single Panel:36" x 102":...)
2235835
2235964
2591388
2591432

# IfcDoor: 38" x 102" (2)
In: Level 15
Type - PredefinedType: DOOR; ParameterTakesPrecedence: no; Material: Steel, Galvanized
Type - Pset_DoorCommon - IsExternal: no; Reference: 38" x 102"
Type - Pset_EnvironmentalImpactIndicators - Reference: 38" x 102"
OverallHeight: 8.53281 ft; OverallWidth: 3.23228 ft
Pset_DoorCommon - IsExternal: yes
Name (Door Single Panel:38" x 102":...)
2234826
2235436

# IfcDoor: 44" x 102", Door Single Panel:44" x 102":2591048
In: Level 15
Type - PredefinedType: DOOR; ParameterTakesPrecedence: no; Material: Steel, Galvanized
Type - Pset_DoorCommon - IsExternal: no; Reference: 44" x 102"
Type - Pset_EnvironmentalImpactIndicators - Reference: 44" x 102"
OverallHeight: 8.53281 ft; OverallWidth: 3.73228 ft
Pset_DoorCommon - IsExternal: yes

# IfcDoor: 74" x 100", Door-Double-Flush_Panel:74" x 100":2590929
In: Level 15
Type - PredefinedType: DOOR; ParameterTakesPrecedence: no; Classification: C1020 Interior Doors (Uniformat); Material: Paint_White
Type - Pset_DoorCommon - IsExternal: no; Reference: 74" x 100"; ThermalTransmittance: 2.19465 kg/K/s3
Type - Pset_EnvironmentalImpactIndicators - Reference: 74" x 100"
OverallHeight: 8.33333 ft; OverallWidth: 6.16667 ft

# IfcDoor: Door-Curtain-Wall-Single-Wood (6)
In: Level 15
Type - PredefinedType: DOOR; ParameterTakesPrecedence: no; Classification: B2030100 Glazed Doors & Entrances (Uniformat); Material: Aluminum, Wood - Birch - Solid Stained Light Low Gloss
Type - Pset_DoorCommon - IsExternal: no; Reference: Door-Curtain-Wall-Single-Wood
Type - Pset_EnvironmentalImpactIndicators - Reference: Door-Curtain-Wall-Single-Wood
OverallHeight: 8.52282 ft; Classification: B2020200 Curtain Walls (Uniformat)
Pset_DoorCommon - IsExternal: yes
Name (Door-Curtain-Wall-Single-Glass:Door-Curtain-Wall-Single-Wood:...) | OverallWidth (ft)
2354289 | 2.7915
2353563 | 2.79167
2352908 | 2.79167
2376198 | 2.7915
2376155 | 2.79167
2376105 | 2.79167

# IfcDoor: Door-Curtain-Wall-Single-Wood, Single-Glass Door:Door-Curtain-Wall-Single-Wood:2589484
In: Level 15
Type - PredefinedType: DOOR; ParameterTakesPrecedence: no; Classification: B2030100 Glazed Doors & Entrances (Uniformat); Material: Glass, Aluminum
Type - Pset_DoorCommon - IsExternal: no; Reference: Door-Curtain-Wall-Single-Wood
Type - Pset_EnvironmentalImpactIndicators - Reference: Door-Curtain-Wall-Single-Wood
OverallHeight: 8.66398 ft; OverallWidth: 3 ft; Classification: B2020200 Curtain Walls (Uniformat)
Pset_DoorCommon - IsExternal: yes

# IfcDoor: M_Door-Curtain-Wall-Double-Glass, M_Door-Curtain-Wall-Double-Glass:M_Door-Curtain-Wall-Double-Glass:2591942
In: Level 15
Type - PredefinedType: DOOR; ParameterTakesPrecedence: no; Classification: B2030100 Glazed Doors & Entrances (Uniformat); Material: Glass, Aluminum
Type - Pset_DoorCommon - IsExternal: no; Reference: M_Door-Curtain-Wall-Double-Glass
Type - Pset_EnvironmentalImpactIndicators - Reference: M_Door-Curtain-Wall-Double-Glass
OverallHeight: 8.67007 ft; OverallWidth: 5.5 ft; Classification: B2020200 Curtain Walls (Uniformat)
Pset_DoorCommon - IsExternal: yes

# IfcDuctFitting: 15 Degree, Rectangular Transition - Angle:15 Degree:2730670
In: Level 15
Type - Pset_DuctFittingTypeCommon - Reference: 15 Degree
Type - Pset_EnvironmentalImpactIndicators - Reference: 15 Degree
Pset_DuctFittingTypeCommon - sets with these values: 2
Group: Mechanical Supply Air 2

# IfcDuctFitting: Standard (9)
In: Level 15
Type - Classification: D3040100 Air Distribution Systems (Uniformat)
Type - Pset_DuctFittingTypeCommon - Reference: Standard
Type - Pset_EnvironmentalImpactIndicators - Reference: Standard
Type - Pset_ManufacturerTypeInformation - Manufacturer: TSI-Standard
Pset_DuctFittingTypeCommon - sets with these values: 2
Name (Rectangular Shoe Tap:Standard:...) | Group
2730181 | Mechanical Supply Air 2
2730184 | Mechanical Supply Air 2
2730196 | Mechanical Supply Air 7
2730201 | Mechanical Supply Air 7
2730202 | Mechanical Supply Air 7
2730212 | Mechanical Supply Air 12
2730215 | Mechanical Supply Air 12
2730218 | Mechanical Supply Air 12
2730675 | Mechanical Supply Air 4

# IfcDuctFitting: Standard (16)
Type - Pset_DuctFittingTypeCommon - Reference: Standard
Type - Pset_EnvironmentalImpactIndicators - Reference: Standard
Pset_DuctFittingTypeCommon - sets with these values: 2
Name | In | Group
Rectangular Endcap:Standard:2730178 | Level 15 | Mechanical Supply Air 2
Rectangular Endcap:Standard:2730189 | Level 15 | Mechanical Supply Air 7
Rectangular Length Eccentric Transition - DTL:Standard:2730192 | Level 15 | Mechanical Supply Air 7
Rectangular Length Eccentric Transition - DTL:Standard:2730193 | Level 15 | Mechanical Supply Air 7
Rectangular Length Eccentric Transition - DTL:Standard:2730204 | Level 15 | Mechanical Supply Air 7
Rectangular Endcap:Standard:2730205 | Level 15 | Mechanical Supply Air 12
Rectangular Endcap:Standard:2730208 | Level 15 | Mechanical Supply Air 12
Rectangular Length Eccentric Transition - DTL:Standard:2730210 | Level 15 | Mechanical Supply Air 12
Rectangular Length Eccentric Transition - DTL:Standard:2730234 | Level 15 | Mechanical Supply Air 16
Rectangular Length Eccentric Transition - DTL:Standard:2730236 | Level 15 | Mechanical Supply Air 16
Rectangular Length Eccentric Transition - DTL:Standard:2730412 | Level 15 | Mechanical Supply Air 16
Rectangular Length Eccentric Transition - DTL:Standard:2730413 | Level 15 | Mechanical Supply Air 16
Rectangular Wye - Curved - Transition:Standard:2730669 | Level 15 | Mechanical Supply Air 5; Mechanical Supply Air 4; Mechanical Supply Air 2
Rectangular Length Eccentric Transition - DTL:Standard:2730673 | Level 15 | Mechanical Supply Air 4
Rectangular Endcap:Standard:2730674 | Level 15 | Mechanical Supply Air 4
Rectangular Length Eccentric Transition - DTL:Standard:2730677 | Level 3 | Mechanical Supply Air 5

# IfcDuctSegment: Rectangular Duct:Square Throat Elbows / S&D (25)
Type - Pset_DuctSegmentTypeCommon - Reference: Square Throat Elbows / S&D
Type - Pset_EnvironmentalImpactIndicators - Reference: Square Throat Elbows / S&D
Pset_DuctSegmentTypeCommon - sets with these values: 2
Name (Rectangular Duct:Square Throat Elbows / S&D:...) | In | Group
2730176 | Level 15 | Mechanical Supply Air 2
2730177 | Level 15 | Mechanical Supply Air 2
2730179 | Level 15 | Mechanical Supply Air 2
2730183 | Level 15 | Mechanical Supply Air 2
2730185 | Level 15 | Mechanical Supply Air 4
2730188 | Level 3 | Mechanical Supply Air 5
2730190 | Level 15 | Mechanical Supply Air 7
2730191 | Level 15 | Mechanical Supply Air 7
2730195 | Level 15 | Mechanical Supply Air 7
2730198 | Level 15 | Mechanical Supply Air 7
2730200 | Level 15 | Mechanical Supply Air 7
2730203 | Level 15 | Mechanical Supply Air 7
2730206 | Level 15 | Mechanical Supply Air 12
2730209 | Level 15 | Mechanical Supply Air 12
2730211 | Level 15 | Mechanical Supply Air 12
2730214 | Level 15 | Mechanical Supply Air 12
2730217 | Level 15 | Mechanical Supply Air 12
2730233 | Level 15 | Mechanical Supply Air 16
2730235 | Level 15 | Mechanical Supply Air 16
2730410 | Level 15 | Mechanical Supply Air 16
2730411 | Level 15 | Mechanical Supply Air 16
2730432 | Level 15 | Mechanical Supply Air 19
2730671 | Level 15 | Mechanical Supply Air 4
2730672 | Level 15 | Mechanical Supply Air 4
2730676 | Level 3 | Mechanical Supply Air 5

# IfcFireSuppressionTerminal: Standard (9)
In: Level 15
Type - Material: Default
Type - Pset_EnvironmentalImpactIndicators - Reference: Standard
Type - Pset_FireSuppressionTerminalTypeCommon - Reference: Standard
Type - Pset_ManufacturerTypeInformation - Manufacturer: Victaulic
Pset_EnvironmentalImpactIndicators - sets with these values: 2
Name (Upright:Standard:...) | Group
2730243 | Fire Protection Wet 2
2730252 | Fire Protection Wet 2
2730261 | Fire Protection Wet 2
2730294 | Fire Protection Wet 2
2730313 | Fire Protection Wet 2
2730322 | Fire Protection Wet 2
2730375 | Fire Protection Wet 2
2730384 | Fire Protection Wet 11
2730454 | Fire Protection Wet 16

# IfcLightFixture: 10, Linear:10:2634411
In: Level 15
Type - Material: Lighting Proxy
Type - Pset_EnvironmentalImpactIndicators - Reference: 10
Type - Pset_LightFixtureTypeCommon - Reference: 10; TotalWattage: 42 W
Type - Pset_LightFixtureTypeSecurityLighting - FixtureHeight: 0.28125 ft
Type - Pset_ManufacturerTypeInformation - Manufacturer: SCHOOLHOUSE ELECTRIC

# IfcLightFixture: 12-6 (3)
In: Level 15
Type - Classification: D5020210 Lighting - Fluorescent (Uniformat); Material: Glass, White, High Luminance, Steel, Paint Finish, Ivory, Glossy
Type - Pset_EnvironmentalImpactIndicators - Reference: 12-6
Type - Pset_LightFixtureTypeCommon - Reference: 12-6
Pset_EnvironmentalImpactIndicators - sets with these values: 2
Name (Ceiling Light - Linear Box:12-6:...)
2645860
2646268
2646331

# IfcLightFixture: 16' (2)
In: Level 15
Type - Classification: D5020210 Lighting - Fluorescent (Uniformat); Material: Glass, White, High Luminance, Steel, Paint Finish, Ivory, Glossy
Type - Pset_EnvironmentalImpactIndicators - Reference: 16'
Type - Pset_LightFixtureTypeCommon - Reference: 16'
Pset_EnvironmentalImpactIndicators - sets with these values: 2
Name (Ceiling Light - Linear Box:16':...)
2644226
2648358

# IfcLightFixture: 20' 3" (2)
In: Level 15
Type - Classification: D5020210 Lighting - Fluorescent (Uniformat); Material: Glass, White, High Luminance, Steel, Paint Finish, Ivory, Glossy
Type - Pset_EnvironmentalImpactIndicators - Reference: 20' 3"
Type - Pset_LightFixtureTypeCommon - Reference: 20' 3"
Pset_EnvironmentalImpactIndicators - sets with these values: 2
Name (Ceiling Light - Linear Box:20' 3":...)
2616530
2634564

# IfcLightFixture: 20' 8" (4)
In: Level 15
Type - Material: Lighting Proxy
Type - Pset_EnvironmentalImpactIndicators - Reference: 20' 8"
Type - Pset_LightFixtureTypeCommon - Reference: 20' 8"; TotalWattage: 42 W
Type - Pset_LightFixtureTypeSecurityLighting - FixtureHeight: 0.28125 ft
Type - Pset_ManufacturerTypeInformation - Manufacturer: SCHOOLHOUSE ELECTRIC
Name (Linear:20' 8":...)
2617290
2634352
2634374
2634393

# IfcLightFixture: Round Ceiling Light (45)
In: Level 15
Type - Material: TRILUX_Alu_RAL_9006, TRILUX_WH_3000_InperlaLP, TRILUX_BR_InperlaLP
Type - Pset_EnvironmentalImpactIndicators - Reference: Round Ceiling Light
Type - Pset_LightFixtureTypeCommon - Reference: Round Ceiling Light
Pset_EnvironmentalImpactIndicators - sets with these values: 2
Name (Round Ceiling Light:Round Ceiling Light:...)
2642526
2642614
2642695
2642750
2642807
2642872
2642874
2642875
2642876
2642877
2642889
2642944
2642991
2643043
2643100
2643161
2643180
2643225
2643266
2643285
2643315
2643362
2643445
2643491
2643562
2643622
2643695
2643761
2643844
2643890
2643984
2644073
2644150
2645126
2645178
2645256
2645257
2645316
2645411
2645462
2645515
2645580
2645619
2645707
2645776

# IfcLightFixture: Vessel Pendant Light (10)
In: Level 15
Type - Classification: E2020200 Furniture & Accessories (Uniformat); Material: Humansclae-Black, Humansclae-LED Light
Type - Pset_EnvironmentalImpactIndicators - Reference: Vessel Pendant Light
Type - Pset_LightFixtureTypeCommon - Reference: Vessel Pendant Light
Type - Pset_ManufacturerTypeInformation - Manufacturer: Humanscale
Pset_EnvironmentalImpactIndicators - sets with these values: 2
Name (Lighting-VSRA-Vessel-Pendant-Light-SM-3D-Humanscale:Vessel Pendant Light:...)
2614193
2616056
2616095
2616136
2616171
2616232
2616281
2616338
2616411
2616454

# IfcMember: 2.5" x 5" rectangular (362)
In: Level 15
Type - PredefinedType: MEMBER; Material: Aluminum
Type - Pset_EnvironmentalImpactIndicators - Reference: 2.5" x 5" rectangular
Type - Pset_MemberCommon - IsExternal: no; Reference: 2.5" x 5" rectangular
PredefinedType: MULLION; Classification: B2020200 Curtain Walls (Uniformat)
Pset_MemberCommon - IsExternal: yes
Name (Rectangular Mullion:2.5" x 5" rectangular:...) | Span (ft)
2238662 | 3.16661
2238663 | 3.4375
2238664 | 9.74877
2238665 | 9.74877
2246153 | 4.79167
2246154 | 4.79167
2246155 | 9.74877
2246217 | 4.79167
2246218 | 3.16661
2246219 | 9.74877
2246290 | 4.79167
2246291 | 4.79167
2246292 | 9.74877
2246438 | 4.79167
2246439 | 4.79167
2246440 | 9.74877
2246536 | 3.4375
2246537 | 4.79167
2246538 | 9.74877
2246864 | 3.16661
2246865 | 3.4375
2246866 | 9.74877
2246867 | 9.74877
2246870 | 4.79167
2246871 | 4.79167
2246872 | 9.74877
2246875 | 4.79167
2246876 | 3.16661
2246877 | 9.74877
2246880 | 4.79167
2246881 | 4.79167
2246882 | 9.74877
2246885 | 4.79167
2246886 | 4.79167
2246887 | 9.74877
2246890 | 3.4375
2246891 | 4.79167
2246892 | 9.74877
2246944 | 3.16661
2246945 | 3.4375
2246946 | 9.74877
2246947 | 9.74877
2246950 | 4.79167
2246951 | 4.79167
2246952 | 9.74877
2246955 | 4.79167
2246956 | 3.16661
2246957 | 9.74877
2246960 | 4.79167
2246961 | 4.79167
2246962 | 9.74877
2246965 | 4.79167
2246966 | 4.79167
2246967 | 9.74877
2246970 | 3.4375
2246971 | 4.79167
2246972 | 9.74877
2247035 | 3.16661
2247036 | 3.4375
2247037 | 9.74877
2247038 | 9.74877
2247041 | 4.79167
2247042 | 4.79167
2247043 | 9.74877
2247046 | 4.79167
2247047 | 3.16661
2247048 | 9.74877
2247051 | 4.79167
2247052 | 4.79167
2247053 | 9.74877
2247056 | 4.79167
2247057 | 4.79167
2247058 | 9.74877
2247061 | 3.4375
2247062 | 4.79167
2247063 | 9.74877
2251184 | 1.47864
2251185 | 1.47864
2251186 | 2.84094
2251187 | 2.84094
2354645 | 2.84094
2354646 | 2.84094
2354647 | 1.47864
2354724 | 2.84094
2354725 | 2.84094
2354726 | 1.47864
2251580 | 1.6875
2251581 | 1.60417
2251582 | 2.84094
2251583 | 2.84094
2353452 | 1.6875
2353453 | 2.84094
2353569 | 2.95833
2353571 | 2.84094
2353728 | 3.04167
2353729 | 2.95833
2353730 | 2.84094
2353821 | 2.875
2353822 | 3.04167
2353823 | 2.84094
2353866 | 2.875
2353867 | 2.875
2353868 | 2.84094
2353921 | 3.04167
2353922 | 2.875
2353923 | 2.84094
2354001 | 2.95833
2354002 | 3.04167
2354003 | 2.84094
2354073 | 2.875
2354074 | 2.95833
2354075 | 2.84094
2354149 | 3.04167
2354150 | 2.875
2354151 | 2.84094
2354224 | 3.04167
2354225 | 2.84094
2354295 | 1.60417
2354297 | 2.84094
2354376 | 2.84094
2354377 | 2.84094
2354378 | 1.60417
2354380 | 3.04167
2354381 | 2.875
2354382 | 2.95833
2354383 | 3.04167
2354384 | 2.875
2354385 | 2.875
2354386 | 3.04167
2354387 | 2.95833
2354389 | 1.6875
2354390 | 2.84094
2354391 | 2.84094
2354392 | 2.84094
2354393 | 2.84094
2354394 | 2.84094
2354395 | 2.84094
2354396 | 2.84094
2354397 | 2.84094
2354398 | 2.84094
2354399 | 2.84094
2354400 | 2.84094
2354501 | 2.84094
2354502 | 2.84094
2354503 | 1.60417
2354505 | 3.04167
2354506 | 2.875
2354507 | 2.95833
2354508 | 3.04167
2354509 | 2.875
2354510 | 2.875
2354511 | 3.04167
2354512 | 2.95833
2354514 | 1.6875
2354515 | 2.84094
2354516 | 2.84094
2354517 | 2.84094
2354518 | 2.84094
2354519 | 2.84094
2354520 | 2.84094
2354521 | 2.84094
2354522 | 2.84094
2354523 | 2.84094
2354524 | 2.84094
2354525 | 2.84094
2251807 | 1.41667
2251808 | 1.41667
2251809 | 2.84094
2251810 | 2.84094
2354968 | 2.84094
2354969 | 2.84094
2354970 | 1.41667
2355045 | 2.84094
2355046 | 2.84094
2355047 | 1.41667
2252627 | 2.66667
2252628 | 1.60417
2252629 | 2.84094
2252630 | 2.84094
2352833 | 2.90283
2352834 | 2.84094
2352914 | 1.60417
2352916 | 2.84094
2352993 | 2.84094
2352994 | 2.84094
2352995 | 1.60417
2352997 | 2.90283
2352998 | 2.84094
2352999 | 2.84094
2353088 | 2.84094
2353089 | 2.84094
2353090 | 1.60417
2353092 | 2.90283
2353093 | 2.84094
2353094 | 2.84094
2353150 | 2.90283
2353151 | 3.03483
2353152 | 3.03483
2353153 | 3.03483
2353154 | 2.84094
2353155 | 2.84094
2353156 | 2.84094
2353347 | 3.03483
2353348 | 2.66667
2353349 | 2.66667
2353350 | 2.66667
2353351 | 2.84094
2353352 | 2.84094
2353353 | 2.84094
2252731 | 1.47864
2252732 | 1.47864
2252733 | 2.84094
2252734 | 2.84094
2354827 | 2.84094
2354828 | 2.84094
2354829 | 1.47864
2354884 | 2.84094
2354885 | 2.84094
2354886 | 1.47864
2376072 | 1.45247
2376073 | 1.45247
2376074 | 2.84094
2376075 | 2.84094
2376275 | 2.84094
2376276 | 2.84094
2376277 | 1.45247
2376280 | 2.84094
2376281 | 2.84094
2376282 | 1.45247
2376078 | 1.73543
2376079 | 1.60417
2376080 | 2.84094
2376081 | 2.84094
2376152 | 1.73543
2376153 | 2.84094
2376156 | 2.95833
2376157 | 2.84094
2376160 | 3.04167
2376161 | 2.95833
2376162 | 2.84094
2376165 | 2.875
2376166 | 3.04167
2376167 | 2.84094
2376170 | 2.875
2376171 | 2.875
2376172 | 2.84094
2376175 | 3.04167
2376176 | 2.875
2376177 | 2.84094
2376180 | 2.95833
2376181 | 3.04167
2376182 | 2.84094
2376185 | 2.875
2376186 | 2.95833
2376187 | 2.84094
2376190 | 3.04167
2376191 | 2.875
2376192 | 2.84094
2376195 | 3.04167
2376196 | 2.84094
2376199 | 1.60417
2376200 | 2.84094
2376214 | 2.84094
2376215 | 2.84094
2376216 | 1.60417
2376217 | 3.04167
2376218 | 2.875
2376219 | 2.95833
2376220 | 3.04167
2376221 | 2.875
2376222 | 2.875
2376223 | 3.04167
2376224 | 2.95833
2376225 | 1.73543
2376226 | 2.84094
2376227 | 2.84094
2376228 | 2.84094
2376229 | 2.84094
2376230 | 2.84094
2376231 | 2.84094
2376232 | 2.84094
2376233 | 2.84094
2376234 | 2.84094
2376235 | 2.84094
2376236 | 2.84094
2376250 | 2.84094
2376251 | 2.84094
2376252 | 1.60417
2376253 | 3.04167
2376254 | 2.875
2376255 | 2.95833
2376256 | 3.04167
2376257 | 2.875
2376258 | 2.875
2376259 | 3.04167
2376260 | 2.95833
2376261 | 1.73543
2376262 | 2.84094
2376263 | 2.84094
2376264 | 2.84094
2376265 | 2.84094
2376266 | 2.84094
2376267 | 2.84094
2376268 | 2.84094
2376269 | 2.84094
2376270 | 2.84094
2376271 | 2.84094
2376272 | 2.84094
2376084 | 1.41667
2376085 | 1.41667
2376086 | 2.84094
2376087 | 2.84094
2376295 | 2.84094
2376296 | 2.84094
2376297 | 1.41667
2376300 | 2.84094
2376301 | 2.84094
2376302 | 1.41667
2376090 | 2.74111
2376091 | 1.55623
2376092 | 2.84094
2376093 | 2.84094
2376102 | 2.90283
2376103 | 2.84094
2376106 | 1.55623
2376107 | 2.84094
2376112 | 2.84094
2376113 | 2.84094
2376114 | 1.55623
2376115 | 2.90283
2376116 | 2.84094
2376117 | 2.84094
2376122 | 2.84094
2376123 | 2.84094
2376124 | 1.55623
2376125 | 2.90283
2376126 | 2.84094
2376127 | 2.84094
2376132 | 2.90283
2376133 | 3.03483
2376134 | 3.03483
2376135 | 3.03483
2376136 | 2.84094
2376137 | 2.84094
2376138 | 2.84094
2376143 | 3.03483
2376144 | 2.74111
2376145 | 2.74111
2376146 | 2.74111
2376147 | 2.84094
2376148 | 2.84094
2376149 | 2.84094
2376096 | 1.51283
2376097 | 1.51283
2376098 | 2.84094
2376099 | 2.84094
2376285 | 2.84094
2376286 | 2.84094
2376287 | 1.51283
2376290 | 2.84094
2376291 | 2.84094
2376292 | 1.51283

# IfcMember: 2.5" x 5" rectangular 2, Rectangular Mullion:2.5" x 5" rectangular 2:2237442
In: Level 15
Type - PredefinedType: MEMBER; Material: Aluminum
Type - Pset_EnvironmentalImpactIndicators - Reference: 2.5" x 5" rectangular 2
Type - Pset_MemberCommon - IsExternal: no; Reference: 2.5" x 5" rectangular 2
PredefinedType: MULLION; Classification: B2020200 Curtain Walls (Uniformat)
Pset_MemberCommon - IsExternal: yes; Span: 8.52282 ft

# IfcOpeningElement: Opening (26)
In: Level 15
Name | PredefinedType | Classification | Reference | sets with these values
Door Single Panel:36" x 102":2235964:1 | OPENING
4 x Basic Wall:Generic - 18":2211392 | OPENING | B2010 Exterior Walls (Uniformat) | Generic - 18" | 2
Door Single Panel:36" x 102":2235835:1 | OPENING
Basic Wall:Generic - 5":2211618 | OPENING | B2010 Exterior Walls (Uniformat) | Generic - 5" | 2
Basic Wall:Generic - 5":2213827 | OPENING | B2010 Exterior Walls (Uniformat) | Generic - 5" | 2
2 x Basic Wall:Generic - 5":2214056 | OPENING | B2010 Exterior Walls (Uniformat) | Generic - 5" | 2
Basic Wall:Generic - 5":2214087 | OPENING | B2010 Exterior Walls (Uniformat) | Generic - 5" | 2
Basic Wall:Generic - 5":2214155 | OPENING | B2010 Exterior Walls (Uniformat) | Generic - 5" | 2
Basic Wall:Generic - 5":2214305 | OPENING | B2010 Exterior Walls (Uniformat) | Generic - 5" | 2
2 x Basic Wall:Generic - 5":2214462 | OPENING | B2010 Exterior Walls (Uniformat) | Generic - 5" | 2
Basic Wall:Generic - 5":2214493 | OPENING | B2010 Exterior Walls (Uniformat) | Generic - 5" | 2
Door Single Panel:38" x 102":2235436:1 | OPENING
Basic Wall:Generic - 5":2214591 | OPENING | B2010 Exterior Walls (Uniformat) | Generic - 5" | 2
Basic Wall:Generic - 8":2236178 | OPENING | B2010 Exterior Walls (Uniformat) | Generic - 8" | 2
Door Single Panel:38" x 102":2234826:1 | OPENING
Door Single Panel:36" x 102":2591432:1 | OPENING
Door Single Panel:36" x 102":2591388:1 | OPENING
Door Single Panel:44" x 102":2591048:1 | OPENING
Door-Double-Flush_Panel:74" x 100":2590929:1 | OPENING
Floor:I-Tile:2531815:2 |  | B1010 Floor Construction (Uniformat) | I-Tile | 2
Basic Wall:Generic - 5":2591597 | OPENING | B2010 Exterior Walls (Uniformat) | Generic - 5" | 2

# IfcOutlet: Duplex-Standard 2 (10)
In: Level 15
Type - PredefinedType: POWEROUTLET
Type - Pset_EnvironmentalImpactIndicators - Reference: Duplex-Standard 2
Type - Pset_OutletTypeCommon - Reference: Duplex-Standard 2
Pset_EnvironmentalImpactIndicators - sets with these values: 2
Name (Power-Recessed-All2:Duplex-Standard 2:...)
2726509
2726763
2726793
2726886
2727049
2727147
2727306
2727372
2727650
2727904

# IfcPipeFitting: Standard (86)
In: Level 15
Type - Pset_EnvironmentalImpactIndicators - Reference: Standard
Type - Pset_PipeFittingTypeCommon - Reference: Standard
Pset_EnvironmentalImpactIndicators - sets with these values: 2
Name | Group
Victaulic Grooved Elbow:Standard:2730223 | Fire Protection Wet 2
Victaulic Grooved Elbow:Standard:2730227 | Fire Protection Wet 2
Victaulic Grooved Elbow:Standard:2730231 | Fire Protection Wet 2
Victaulic Grooved Tee:Standard:2730237 | Fire Protection Wet 2
Victaulic Grooved Elbow:Standard:2730241 | Fire Protection Wet 2
Victaulic Grooved Tee:Standard:2730248 | Fire Protection Wet 2
Victaulic Grooved Tee:Standard:2730257 | Fire Protection Wet 2
Victaulic Grooved Elbow:Standard:2730264 | Fire Protection Wet 2
Victaulic Grooved Elbow:Standard:2730270 | Fire Protection Wet 2
Victaulic Grooved Elbow:Standard:2730274 | Fire Protection Wet 2
Victaulic Grooved Elbow:Standard:2730276 | Fire Protection Wet 2
Victaulic Grooved Tee:Standard:2730282 | Fire Protection Wet 2
Victaulic Grooved Tee:Standard:2730290 | Fire Protection Wet 2
Victaulic Grooved Elbow:Standard:2730297 | Fire Protection Wet 2
Victaulic Grooved Elbow:Standard:2730301 | Fire Protection Wet 2
Victaulic Grooved Elbow:Standard:2730307 | Fire Protection Wet 2
Victaulic Grooved Elbow:Standard:2730309 | Fire Protection Wet 2
Victaulic Grooved Tee:Standard:2730318 | Fire Protection Wet 2
Victaulic Grooved Elbow:Standard:2730325 | Fire Protection Wet 2
Victaulic Grooved Elbow:Standard:2730333 | Fire Protection Wet 2
Victaulic Grooved Elbow:Standard:2730335 | Fire Protection Wet 2
Victaulic Grooved Elbow:Standard:2730337 | Fire Protection Wet 2
Victaulic Grooved Elbow:Standard:2730343 | Fire Protection Wet 2
Victaulic Grooved Elbow:Standard:2730347 | Fire Protection Wet 2
Victaulic Grooved Elbow:Standard:2730349 | Fire Protection Wet 2
Victaulic Grooved Elbow:Standard:2730351 | Fire Protection Wet 2
Victaulic Grooved Elbow:Standard:2730355 | Fire Protection Wet 2
Victaulic Grooved Elbow:Standard:2730361 | Fire Protection Wet 2
Victaulic Grooved Elbow:Standard:2730363 | Fire Protection Wet 2
Victaulic Grooved Elbow:Standard:2730367 | Fire Protection Wet 2
Victaulic Grooved Elbow:Standard:2730371 | Fire Protection Wet 2
Victaulic Grooved Elbow:Standard:2730373 | Fire Protection Wet 2
Victaulic Grooved Tee:Standard:2730378 | Fire Protection Wet 2
Victaulic Grooved Elbow:Standard:2730387 | Fire Protection Wet 11
Victaulic Grooved Elbow:Standard:2730391 | Fire Protection Wet 11
Victaulic Grooved Tee:Standard:2730399 | Fire Protection Wet 2
Victaulic Grooved Tee:Standard:2730403 | Fire Protection Wet 2
Threaded Elbow:Standard:2730420 | Hydronic Supply 1
Threaded Elbow:Standard:2730422 | Hydronic Supply 1
Threaded Elbow:Standard:2730426 | Hydronic Supply 1
Threaded Elbow:Standard:2730430 | Hydronic Supply 1
Victaulic Grooved Elbow:Standard:2730436 | Fire Protection Wet 2
Victaulic Grooved Elbow:Standard:2730440 | Fire Protection Wet 2
Victaulic Grooved Elbow:Standard:2730446 | Fire Protection Wet 14
Victaulic Grooved Elbow:Standard:2730450 | Fire Protection Wet 14
Victaulic Grooved Elbow:Standard:2730457 | Fire Protection Wet 16
Victaulic Grooved Elbow:Standard:2730461 | Fire Protection Wet 14
Threaded Tee:Standard:2730467 | Other 1
Threaded Elbow:Standard:2730473 | Other 1
Threaded Elbow:Standard:2730475 | Other 1
Threaded Elbow:Standard:2730483 | Other 1
Threaded Elbow:Standard:2730485 | Other 1
Threaded Elbow:Standard:2730489 | Other 1
Threaded Elbow:Standard:2730491 | Other 1
Threaded Elbow:Standard:2730495 | Hydronic Supply 1
Threaded Elbow:Standard:2730499 | Hydronic Supply 1
Threaded Elbow:Standard:2730507 | Hydronic Supply 3
Threaded Elbow:Standard:2730509 | Hydronic Supply 3
Threaded Elbow:Standard:2730513 | Hydronic Supply 3
Threaded Elbow:Standard:2730517 | Hydronic Supply 3
Threaded Elbow:Standard:2730521 | Hydronic Supply 3
Threaded Elbow:Standard:2730525 | Hydronic Supply 3
Threaded Elbow:Standard:2730531 | Hydronic Supply 1
Threaded Elbow:Standard:2730535 | Hydronic Supply 1
Threaded Elbow:Standard:2730539 | Hydronic Supply 1
Threaded Tee:Standard:2730543 | Hydronic Supply 1
Threaded Elbow:Standard:2730547 | Hydronic Supply 1
Threaded Elbow:Standard:2730553 | Hydronic Supply 3
Threaded Elbow:Standard:2730557 | Hydronic Supply 3
Threaded Elbow:Standard:2730561 | Hydronic Supply 3
Threaded Elbow:Standard:2730567 | Hydronic Supply 3
Threaded Elbow:Standard:2730571 | Hydronic Supply 3
Threaded Tee:Standard:2730573 | Hydronic Supply 3
Threaded Elbow:Standard:2730577 | Hydronic Supply 3
Threaded Elbow:Standard:2730583 | Hydronic Supply 7
Threaded Elbow:Standard:2730589 | Hydronic Supply 9
Threaded Tee:Standard:2730612 | Other 4
Threaded Elbow:Standard:2730618 | Other 4
Threaded Tee:Standard:2730628 | Other 4
Threaded Elbow:Standard:2730632 | Other 4
Threaded Tee:Standard:2730634 | Other 4
Threaded Elbow:Standard:2730638 | Other 4
Threaded Tee:Standard:2730644 | Other 4
Threaded Elbow:Standard:2730648 | Other 4
Threaded Tee:Standard:2730654 | Other 4
Threaded Elbow:Standard:2730658 | Other 4

# IfcPipeSegment: Pipe Types:Fire Prot Sched 10 Main (55)
In: Level 15
Type - Pset_EnvironmentalImpactIndicators - Reference: Fire Prot Sched 10 Main
Type - Pset_PipeSegmentTypeCommon - Reference: Fire Prot Sched 10 Main
Pset_EnvironmentalImpactIndicators - sets with these values: 2
Pset_PipeSegmentTypeGutter - Slope: 0 deg
Name (Pipe Types:Fire Prot Sched 10 Main:...) | InvertElevation (ft) | Group
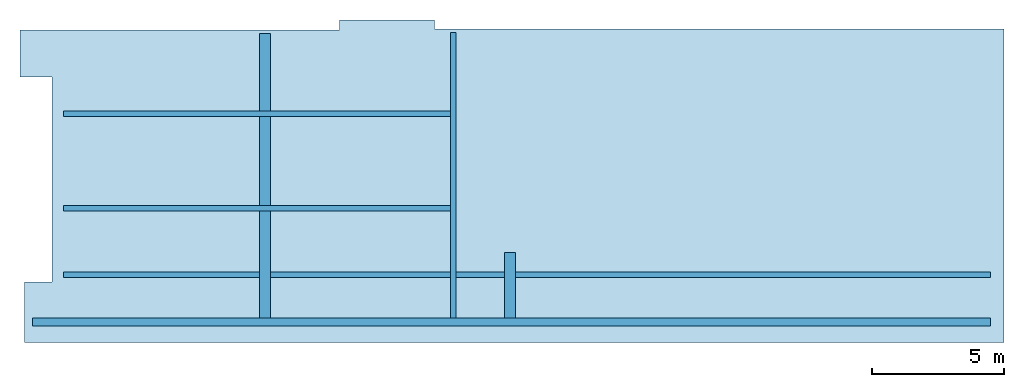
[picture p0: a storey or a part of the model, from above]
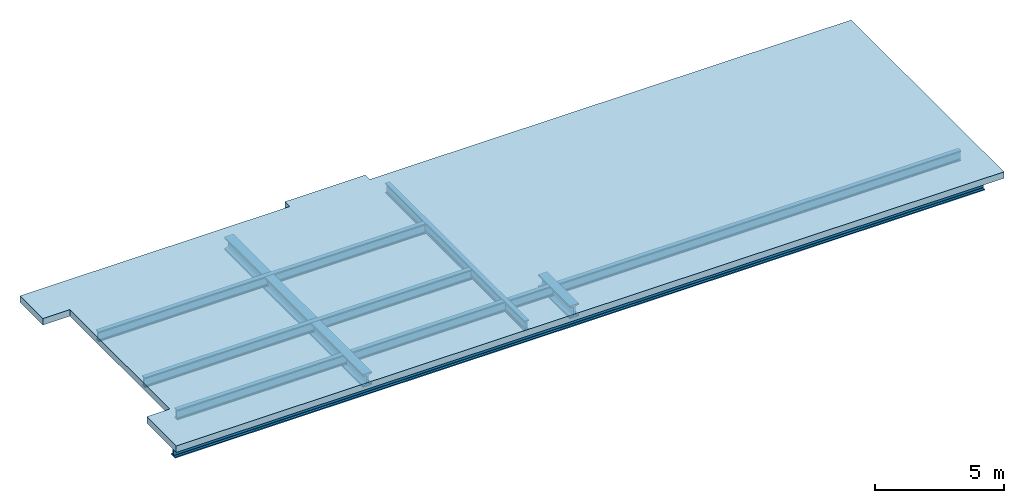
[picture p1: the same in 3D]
Properties of the parts of a building model (IFC4), part 2 of 2

# IfcPipeSegment: Pipe Types:Fire Prot Sched 10 Main (55)
Name (Pipe Types:Fire Prot Sched 10 Main:...) | InvertElevation (ft) | Group
2730219 | 176.872 | Fire Protection Wet 2
2730221 | 176.788 | Fire Protection Wet 2
2730225 | 176.623 | Fire Protection Wet 2
2730229 | 176.788 | Fire Protection Wet 2
2730238 | 176.872 | Fire Protection Wet 2
2730244 | 177.116 | Fire Protection Wet 2
2730246 | 176.956 | Fire Protection Wet 2
2730249 | 176.956 | Fire Protection Wet 2
2730253 | 177.825 | Fire Protection Wet 2
2730255 | 177.665 | Fire Protection Wet 2
2730258 | 177.665 | Fire Protection Wet 2
2730262 | 177.816 | Fire Protection Wet 2
2730266 | 176.725 | Fire Protection Wet 2
2730268 | 176.56 | Fire Protection Wet 2
2730272 | 176.725 | Fire Protection Wet 2
2730278 | 177.116 | Fire Protection Wet 2
2730280 | 176.956 | Fire Protection Wet 2
2730283 | 176.956 | Fire Protection Wet 2
2730286 | 177.997 | Fire Protection Wet 2
2730288 | 178.206 | Fire Protection Wet 2
2730291 | 177.831 | Fire Protection Wet 2
2730295 | 178.358 | Fire Protection Wet 2
2730299 | 177.121 | Fire Protection Wet 2
2730303 | 176.623 | Fire Protection Wet 2
2730305 | 176.788 | Fire Protection Wet 2
2730311 | 176.956 | Fire Protection Wet 2
2730314 | 178.325 | Fire Protection Wet 2
2730316 | 176.831 | Fire Protection Wet 2
2730319 | 178.165 | Fire Protection Wet 2
2730323 | 176.983 | Fire Protection Wet 2
2730327 | 177.831 | Fire Protection Wet 2
2730329 | 177.996 | Fire Protection Wet 2
2730331 | 177.831 | Fire Protection Wet 2
2730339 | 177.194 | Fire Protection Wet 2
2730341 | 177.029 | Fire Protection Wet 2
2730345 | 179.331 | Fire Protection Wet 2
2730353 | 179.331 | Fire Protection Wet 2
2730357 | 178.165 | Fire Protection Wet 2
2730359 | 176.996 | Fire Protection Wet 2
2730365 | 176.956 | Fire Protection Wet 2
2730369 | 176.788 | Fire Protection Wet 2
2730376 | 177.116 | Fire Protection Wet 2
2730379 | 176.956 | Fire Protection Wet 2
2730382 | 178.331 | Fire Protection Wet 11
2730385 | 178.483 | Fire Protection Wet 11
2730389 | 178.331 | Fire Protection Wet 11
2730400 | 176.872 | Fire Protection Wet 2
2730404 | 176.872 | Fire Protection Wet 2
2730434 | 176.872 | Fire Protection Wet 2
2730438 | 176.872 | Fire Protection Wet 2
2730444 | 177.165 | Fire Protection Wet 14
2730448 | 177.165 | Fire Protection Wet 14
2730452 | 178.123 | Fire Protection Wet 16
2730455 | 178.274 | Fire Protection Wet 16
2730459 | 177.165 | Fire Protection Wet 14

# IfcPipeSegment: Pipe Types:Hydronic (57)
In: Level 15
Type - Pset_EnvironmentalImpactIndicators - Reference: Hydronic
Type - Pset_PipeSegmentTypeCommon - Reference: Hydronic
Pset_EnvironmentalImpactIndicators - sets with these values: 2
Name (Pipe Types:Hydronic:...) | InvertElevation (ft) | Slope (deg) | Group
2730414 | 179.082 | 0 | Hydronic Supply 1
2730416 | 177.374 | 0 | Hydronic Supply 1
2730418 | 177.86 | 0 | Hydronic Supply 1
2730424 | 177.863 | 0 | Hydronic Supply 1
2730428 | 178.832 | 0 | Hydronic Supply 1
2730442 | 177.585 | 0 | Other 1
2730463 | 177.585 | 0 | Other 1
2730465 | 177.585 | 0 | Other 1
2730468 | 177.585 | 0 | Other 1
2730471 | 177.71 | 0 | Other 1
2730477 | 177.585 | 0 | Other 1
2730479 | 177.877 | 0 | Other 1
2730481 | 177.73 | 6.02203 | Other 1
2730487 | 177.605 | 6.02203 | Other 1
2730493 | 177.901 | 0 | Hydronic Supply 1
2730497 | 177.416 | 0 | Hydronic Supply 1
2730501 | 179.082 | 0 | Hydronic Supply 3
2730503 | 177.374 | 0 | Hydronic Supply 3
2730505 | 177.86 | 0 | Hydronic Supply 3
2730511 | 177.863 | 0 | Hydronic Supply 3
2730515 | 178.832 | 0 | Hydronic Supply 3
2730519 | 177.901 | 0 | Hydronic Supply 3
2730523 | 177.416 | 0 | Hydronic Supply 3
2730527 | 177.374 | 0 | Hydronic Supply 1
2730529 | 177.374 | 0 | Hydronic Supply 1
2730533 | 177.863 | 0 | Hydronic Supply 1
2730537 | 178.499 | 0 | Hydronic Supply 1
2730541 | 177.863 | 0 | Hydronic Supply 1
2730544 | 177.374 | 0 | Hydronic Supply 1
2730549 | 177.374 | 0 | Hydronic Supply 3
2730551 | 177.374 | 0 | Hydronic Supply 3
2730555 | 177.863 | 0 | Hydronic Supply 3
2730559 | 178.499 | 0 | Hydronic Supply 3
2730563 | 177.863 | 0 | Hydronic Supply 3
2730565 | 177.863 | 0 | Hydronic Supply 3
2730569 | 178.624 | 0 | Hydronic Supply 3
2730574 | 177.374 | 0 | Hydronic Supply 3
2730579 | 177.206 | 0 | Hydronic Supply 7
2730581 | 177.206 | 0 | Hydronic Supply 7
2730585 | 177.206 | 0 | Hydronic Supply 9
2730587 | 177.206 | 0 | Hydronic Supply 9
2730608 | 176.836 | 0 | Other 4
2730610 | 177.618 | 42.6181 | Other 4
2730613 | 176.836 | 0 | Other 4
2730616 | 179.944 | 0 | Other 4
2730620 | 177.618 | 42.6181 | Other 4
2730622 | 179.941 | 0 | Other 4
2730624 | 177.618 | 42.6181 | Other 4
2730626 | 179.894 | 0 | Other 4
2730629 | 176.836 | 0 | Other 4
2730635 | 176.836 | 0 | Other 4
2730640 | 177.781 | 0 | Other 4
2730642 | 177.081 | 0 | Other 4
2730645 | 176.836 | 0 | Other 4
2730650 | 177.781 | 0 | Other 4
2730652 | 177.081 | 0 | Other 4
2730655 | 176.836 | 0 | Other 4

# IfcPlate: Glazed (136)
In: Level 15
Type - PredefinedType: CURTAIN_PANEL; Material: <Unnamed> 0.0833333 ft
Type - Pset_EnvironmentalImpactIndicators - Reference: Glazed
Type - Pset_PlateCommon - IsExternal: no; Reference: Glazed; ThermalTransmittance: 6.7069 kg/K/s3
Classification: B2020200 Curtain Walls (Uniformat)
Pset_PlateCommon - IsExternal: yes
Name (System Panel:Glazed:...)
2237437
2237934
2238086
2238196
2238295
2238390
2238659
2246530
2246432
2246284
2246146
2246211
2246863
2246889
2246884
2246879
2246869
2246874
2246943
2246969
2246964
2246959
2246949
2246954
2247034
2247060
2247055
2247050
2247040
2247045
2251182
2354717
2354638
2251578
2354217
2354143
2354067
2353995
2353915
2353860
2353815
2353722
2353444
2354470
2354472
2354473
2354474
2354475
2354476
2354477
2354478
2354479
2354481
2354340
2354342
2354343
2354344
2354345
2354346
2354347
2354348
2354349
2354351
2251803
2355038
2354961
2252625
2352825
2353136
2353333
2353073
2353075
2353137
2353334
2352977
2352979
2353138
2353335
2252728
2354877
2354820
2376071
2376279
2376274
2376077
2376194
2376189
2376184
2376179
2376174
2376169
2376164
2376159
2376151
2376238
2376240
2376241
2376242
2376243
2376244
2376245
2376246
2376247
2376249
2376202
2376204
2376205
2376206
2376207
2376208
2376209
2376210
2376211
2376213
2376083
2376299
2376294
2376089
2376101
2376129
2376140
2376119
2376121
2376130
2376141
2376109
2376111
2376131
2376142
2376095
2376289
2376284
2589336
2589437
2591837
2592003

# IfcSlab: Floor:Generic - 12", Floor:Generic - 12":2215175
In: Level 15
Type - PredefinedType: FLOOR; Material: Default Floor 1 ft
Type - Pset_EnvironmentalImpactIndicators - Reference: Generic - 12"
Type - Pset_ReinforcementBarPitchOfSlab - Reference: Generic - 12"
Type - Pset_SlabCommon - IsExternal: no; Reference: Generic - 12"
Classification: B1010 Floor Construction (Uniformat)
Pset_EnvironmentalImpactIndicators - sets with these values: 2
Pset_SlabCommon - LoadBearing: no; PitchAngle: 0 deg

# IfcSlab: Floor:Generic Struc- 12", Floor:Generic Struc- 12":2722472
In: Level 16
Type - PredefinedType: FLOOR; Material: Default Floor 1 ft, Default Floor 0 ft
Type - Pset_EnvironmentalImpactIndicators - Reference: Generic Struc- 12"
Type - Pset_ReinforcementBarPitchOfSlab - Reference: Generic Struc- 12"
Type - Pset_SlabCommon - IsExternal: no; Reference: Generic Struc- 12"
Classification: B1010 Floor Construction (Uniformat)
Pset_EnvironmentalImpactIndicators - sets with these values: 2
Pset_SlabCommon - PitchAngle: 0 deg; LoadBearing: yes

# IfcSlab: Floor:I-Carpet (4)
In: Level 15
Type - PredefinedType: FLOOR; Material: Carpet 0.0416667 ft
Type - Pset_EnvironmentalImpactIndicators - Reference: I-Carpet
Type - Pset_ReinforcementBarPitchOfSlab - Reference: I-Carpet
Type - Pset_SlabCommon - IsExternal: no; Reference: I-Carpet
Classification: B1010 Floor Construction (Uniformat)
Pset_EnvironmentalImpactIndicators - sets with these values: 2
Pset_SlabCommon - LoadBearing: no; PitchAngle: 0 deg
Name (Floor:I-Carpet:...)
2426394
2426440
2426447
2532235

# IfcSlab: Floor:I-Hardwood, Floor:I-Hardwood:2531397
In: Level 15
Type - PredefinedType: FLOOR; Material: Oak Flooring 0.0416667 ft
Type - Pset_EnvironmentalImpactIndicators - Reference: I-Hardwood
Type - Pset_ReinforcementBarPitchOfSlab - Reference: I-Hardwood
Type - Pset_SlabCommon - IsExternal: no; Reference: I-Hardwood; ThermalTransmittance: 14.1732 kg/K/s3
Classification: B1010 Floor Construction (Uniformat)
Pset_EnvironmentalImpactIndicators - sets with these values: 2
Pset_SlabCommon - LoadBearing: no; PitchAngle: 0 deg

# IfcSlab: Floor:I-Tile, Floor:I-Tile:2531815
In: Level 15
Type - PredefinedType: FLOOR; Material: Tile 4x4 0.0416667 ft
Type - Pset_EnvironmentalImpactIndicators - Reference: I-Tile
Type - Pset_ReinforcementBarPitchOfSlab - Reference: I-Tile
Type - Pset_SlabCommon - IsExternal: no; Reference: I-Tile; ThermalTransmittance: 94.4882 kg/K/s3
Classification: B1010 Floor Construction (Uniformat)
Pset_EnvironmentalImpactIndicators - sets with these values: 2
Pset_SlabCommon - LoadBearing: no; PitchAngle: 0 deg

# IfcWall: Basic Wall:Generic - 12", Basic Wall:Generic - 12":2211503
In: Level 15
Type - Material: Default Wall 1 ft
Type - Pset_EnvironmentalImpactIndicators - Reference: Generic - 12"
Type - Pset_ReinforcementBarPitchOfWall - Reference: Generic - 12"
Type - Pset_WallCommon - IsExternal: no; Reference: Generic - 12"
Classification: B2010 Exterior Walls (Uniformat)
Pset_EnvironmentalImpactIndicators - sets with these values: 2
Pset_WallCommon - LoadBearing: no; ExtendToStructure: no; IsExternal: yes

# IfcWall: Basic Wall:Generic - 18", Basic Wall:Generic - 18":2211392
In: Level 15
Type - Material: Default Wall 1.5 ft
Type - Pset_EnvironmentalImpactIndicators - Reference: Generic - 18"
Type - Pset_ReinforcementBarPitchOfWall - Reference: Generic - 18"
Type - Pset_WallCommon - IsExternal: no; Reference: Generic - 18"
Classification: B2010 Exterior Walls (Uniformat)
Pset_EnvironmentalImpactIndicators - sets with these values: 2
Pset_WallCommon - LoadBearing: no; ExtendToStructure: no; IsExternal: yes

# IfcWall: Basic Wall:Generic - 3" (2)
In: Level 15
Type - Material: Default Wall 0.25 ft
Type - Pset_EnvironmentalImpactIndicators - Reference: Generic - 3"
Type - Pset_ReinforcementBarPitchOfWall - Reference: Generic - 3"
Type - Pset_WallCommon - IsExternal: no; Reference: Generic - 3"
Classification: B2010 Exterior Walls (Uniformat)
Pset_EnvironmentalImpactIndicators - sets with these values: 2
Pset_WallCommon - LoadBearing: no; ExtendToStructure: no
Name (Basic Wall:Generic - 3":...)
2594162
2594238

# IfcWall: Basic Wall:Generic - 5" (22)
In: Level 15
Type - Material: Default Wall 0.416667 ft
Type - Pset_EnvironmentalImpactIndicators - Reference: Generic - 5"
Type - Pset_ReinforcementBarPitchOfWall - Reference: Generic - 5"
Type - Pset_WallCommon - Reference: Generic - 5"; IsExternal: no
Classification: B2010 Exterior Walls (Uniformat)
Pset_EnvironmentalImpactIndicators - sets with these values: 2
Pset_WallCommon - LoadBearing: no; ExtendToStructure: no
Name (Basic Wall:Generic - 5":...)
2210903
2210985
2211082
2211173
2211240
2211618
2211775
2212897
2212984
2213204
2213426
2213521
2213614
2213827
2214056
2214087
2214155
2214305
2214462
2214493
2214591
2591597

# IfcWall: Basic Wall:Generic - 6" (2)
In: Level 15
Type - Material: Default Wall 0.5 ft
Type - Pset_EnvironmentalImpactIndicators - Reference: Generic - 6"
Type - Pset_ReinforcementBarPitchOfWall - Reference: Generic - 6"
Type - Pset_WallCommon - IsExternal: no; Reference: Generic - 6"
Classification: B2010 Exterior Walls (Uniformat)
Pset_EnvironmentalImpactIndicators - sets with these values: 2
Pset_WallCommon - LoadBearing: no; ExtendToStructure: no; IsExternal: yes
Name (Basic Wall:Generic - 6":...)
2211709
2211927

# IfcWall: Basic Wall:Generic - 8", Basic Wall:Generic - 8":2236178
In: Level 15
Type - Material: Default Wall 0.666667 ft
Type - Pset_EnvironmentalImpactIndicators - Reference: Generic - 8"
Type - Pset_ReinforcementBarPitchOfWall - Reference: Generic - 8"
Type - Pset_WallCommon - IsExternal: no; Reference: Generic - 8"
Classification: B2010 Exterior Walls (Uniformat)
Pset_EnvironmentalImpactIndicators - sets with these values: 2
Pset_WallCommon - LoadBearing: no; ExtendToStructure: no; IsExternal: yes

# IfcWall: Basic Wall:Generic - 9' (3)
In: Level 15
Type - Material: Default Wall 0.75 ft
Type - Pset_EnvironmentalImpactIndicators - Reference: Generic - 9'
Type - Pset_ReinforcementBarPitchOfWall - Reference: Generic - 9'
Type - Pset_WallCommon - IsExternal: no; Reference: Generic - 9'
Classification: B2010 Exterior Walls (Uniformat)
Pset_EnvironmentalImpactIndicators - sets with these values: 2
Pset_WallCommon - LoadBearing: no; ExtendToStructure: no; IsExternal: yes
Name (Basic Wall:Generic - 9':...)
2213069
2213313
2213751
